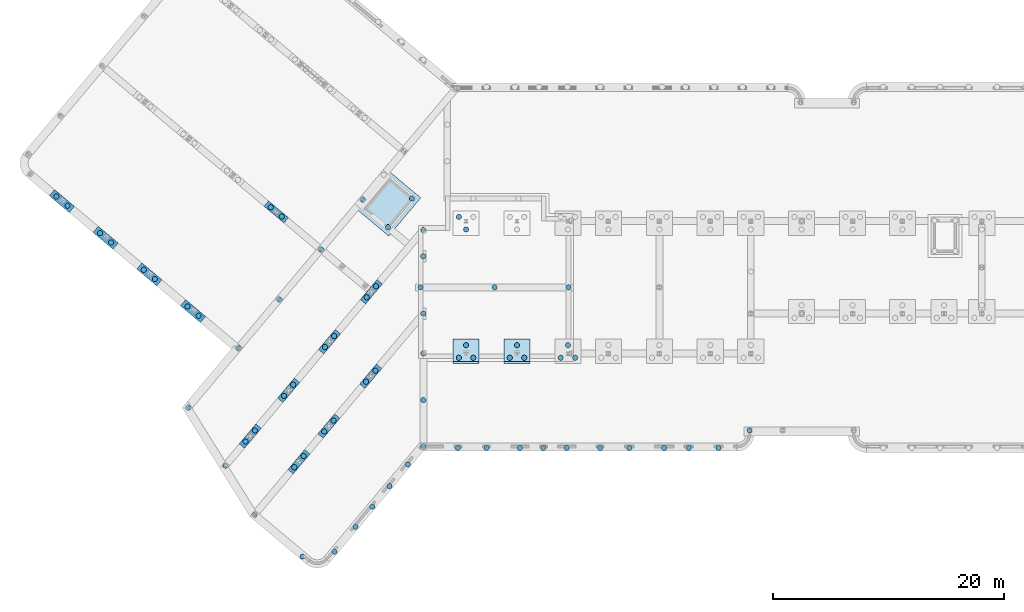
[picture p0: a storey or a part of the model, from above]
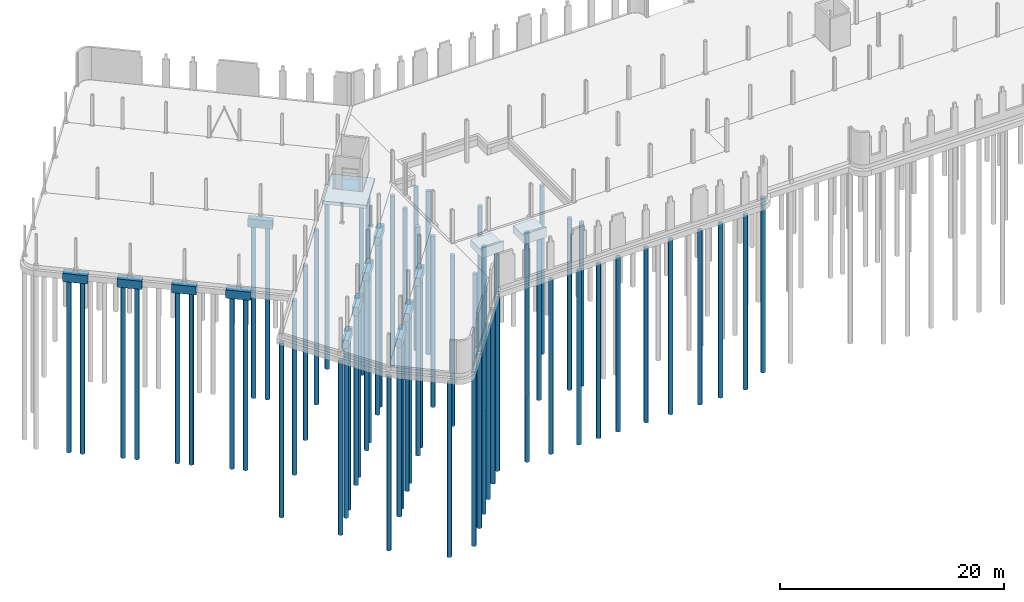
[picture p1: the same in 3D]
Properties of the parts of a building model (IFC2X3), part 1 of 3

# File
Description: ViewDefinition [CoordinationView_V2.0, QuantityTakeOffAddOnView], RevitIdentifiers [ContentGUID: 3bbd01f3-17ad-4578-aeb0-1501959cfa29, VersionGUID: ad77fbda-3d01-4379-a9cd-0f24ddc18399, NumberOfSaves: 457]
File name: MM25146_MFA Rijpelberg Helmond.ifc
Time: 2026-06-18T10:10:07+01:00
Written by: ODA SDAI 24.6
Made in: Autodesk Revit 24.3.0.13 (ENU) - IFC 24.3.0.13

# IfcProject, MM25146
LongName: MFA Rijpelberg; Phase: Project Status

# IfcSite, Default
RefLatitude: 42, 23, 13, 199999; RefLongitude: -71, -14, -31, -199999; RefElevation: 0 mm

# IfcSite: NLRS_00_GM_nulpunt_banier_blok_AT:nulpunt, NLRS_00_GM_nulpunt_banier_blok_AT:nulpunt:329284
Material: z9_Tielemans-grijs, z9_Tielemans-geel, z9_Tielemans-l-grijs
BaseQuantities - GrossArea: 4.78253 m2

# IfcBuilding, AT constructie
LongName: AT constructie

# IfcBuildingStorey: Level:A_hoogte_2.0mm (6)
In: AT constructie
Name | LongName | Elevation (mm)
-01 kelder | -01 kelder | -3500
00 begane grond | 00 begane grond | -1.08287e-12
01 eerste verdieping | 01 eerste verdieping | 3864
02 tweede verdieping | 02 tweede verdieping | 7728
03 derde verdieping | 03 derde verdieping | 12043
04 vierde verdieping | 04 vierde verdieping | 15456

# IfcBeam: balk HE_gen_HEA180 (37)
Classification: 28.11 hoofddraagconstructies; kolommen en liggers, kolom-/liggerconstructies (Uniformat); Material: h2_staal_S355
Tielemans_Framing_PSET - Soortelijk_gewicht: 8000 kg/m3; Type: balk HE_gen_HEA180; Description: HEA180; Structural Material: h2_staal_S355; Assembly Code: 28.11; Assembly Description: hoofddraagconstructies; kolommen en liggers, kolom-/liggerconstructies; Phase Created: 2. nieuwbouw; Staalkwaliteit: S355
Name (NLRS_28_SF_LIB_balk HEA_gen_AT:balk HE_gen_HEA180:...) | In | Length (mm) | CrossSectionArea (m2) | OuterSurfaceArea (m2) | GrossVolume (m3) | NetVolume (m3) = Volume (m3) | Massa (kg)
860012 | 01 eerste verdieping | 5893.25 | 0.00452527 | 6.03615 | 0.0266686 | 0.026668 | 213.344
911190 | 02 tweede verdieping | 23195 | 0.00452527 | 23.7574 | 0.104964 | 0.104961 | 839.691
911191 | 02 tweede verdieping | 20800 | 0.00452527 | 21.3044 | 0.0941257 | 0.0941235 | 752.988
913779 | 01 eerste verdieping | 20770 | 0.00452527 | 21.2736 | 0.0939899 | 0.0939878 | 751.902
917035 | 02 tweede verdieping | 4730 | 0.00452527 | 4.84469 | 0.0214045 | 0.0214041 | 171.232
918010 | 02 tweede verdieping |  |  |  |  | 0.00788246 | 63.0597 | BaseQuantities - GrossSurfaceArea: 0 m2
919803 | 02 tweede verdieping | 4730 | 0.00452527 | 4.84469 | 0.0214045 | 0.0214041 | 171.232
927900 | 02 tweede verdieping | 5573.25 | 0.00452527 | 5.70839 | 0.0252205 | 0.0252199 | 201.759
931741 | 03 derde verdieping | 9724.56 | 0.00452527 | 9.96036 | 0.0440063 | 0.0440053 | 352.042
931742 | 03 derde verdieping |  |  |  |  | 0.00806824 | 64.5459 | BaseQuantities - GrossSurfaceArea: 0 m2
932789 | 03 derde verdieping | 23440 | 0.00452527 | 24.0084 | 0.106072 | 0.10607 | 848.56
933283 | 03 derde verdieping |  |  |  |  | 0.00751662 | 60.1329 | BaseQuantities - GrossSurfaceArea: 0 m2
933658 | 03 derde verdieping | 11150 | 0.00452527 | 11.4204 | 0.0504569 | 0.0504557 | 403.646
943029 | 01 eerste verdieping | 11069 | 0.00452527 | 11.3374 | 0.0500904 | 0.0500893 | 400.714
957652 | 03 derde verdieping | 17066.3 | 0.00452527 | 17.4801 | 0.0772295 | 0.0772278 | 617.822
959066 | 03 derde verdieping | 10926.4 | 0.00452527 | 11.1913 | 0.0494449 | 0.0494438 | 395.55
959180 | 03 derde verdieping | 23215 | 0.00452527 | 23.7779 | 0.105054 | 0.105052 | 840.415
960760 | 03 derde verdieping |  |  |  |  | 0.00790709 | 63.2567 | BaseQuantities - GrossSurfaceArea: 0 m2
961026 | 03 derde verdieping | 8920 | 0.00452527 | 9.13629 | 0.0403654 | 0.0403645 | 322.916
961942 | 03 derde verdieping | 9849.99 | 0.00452527 | 10.0888 | 0.0445739 | 0.0445729 | 356.583
964484 | 03 derde verdieping | 16851.2 | 0.00452527 | 17.2598 | 0.0762563 | 0.0762546 | 610.037
964938 | 03 derde verdieping | 8920 | 0.00452527 | 9.13629 | 0.0403654 | 0.0403645 | 322.916
965281 | 03 derde verdieping |  |  |  |  | 0.00789343 | 63.1475 | BaseQuantities - GrossSurfaceArea: 0 m2
969872 | 03 derde verdieping | 11150 | 0.00452527 | 11.4204 | 0.0504569 | 0.0504557 | 403.646
969873 | 03 derde verdieping | 12611.9 | 0.00452527 | 12.9177 | 0.0570723 | 0.057071 | 456.568
980927 | 03 derde verdieping |  |  |  |  | 0.00787984 | 63.0387 | BaseQuantities - GrossSurfaceArea: 0 m2
980930 | 03 derde verdieping | 3475.1 | 0.00452527 | 3.55936 | 0.0157258 | 0.0157254 | 125.803
981139 | 03 derde verdieping | 5334.1 | 0.00452527 | 5.46344 | 0.0241383 | 0.0241377 | 193.102
981366 | 03 derde verdieping | 4194.6 | 0.00452527 | 4.29631 | 0.0189817 | 0.0189813 | 151.85
981455 | 03 derde verdieping | 5434.6 | 0.00452527 | 5.56638 | 0.0245931 | 0.0245925 | 196.74
981598 | 03 derde verdieping |  |  |  |  | 0.00787984 | 63.0387 | BaseQuantities - GrossSurfaceArea: 0 m2
981675 | 03 derde verdieping |  |  |  |  | 0.00787984 | 63.0387 | BaseQuantities - GrossSurfaceArea: 0 m2
981676 | 03 derde verdieping | 5434.6 | 0.00452527 | 5.56638 | 0.0245931 | 0.0245925 | 196.74
981677 | 03 derde verdieping |  |  |  |  | 0.00787984 | 63.0387 | BaseQuantities - GrossSurfaceArea: 0 m2
981806 | 03 derde verdieping | 3475.1 | 0.00452527 | 3.55936 | 0.0157258 | 0.0157254 | 125.803
981807 | 03 derde verdieping | 5334.1 | 0.00452527 | 5.46344 | 0.0241383 | 0.0241377 | 193.102
981808 | 03 derde verdieping | 4194.6 | 0.00452527 | 4.29631 | 0.0189817 | 0.0189813 | 151.85

# IfcBeam: balk HE_gen_HEB180 (5)
Classification: 28.11.21 (Uniformat); Material: h2_staal_S355
BaseQuantities - CrossSectionArea: 0.00652527 m2
Tielemans_Framing_PSET - Soortelijk_gewicht: 8000 kg/m3; Type: balk HE_gen_HEB180; Description: HEB180; Structural Material: h2_staal_S355; Assembly Code: 28.11.21; Phase Created: 2. nieuwbouw; Staalkwaliteit: S355
Name (NLRS_28_SF_LIB_balk HEB_gen_AT:balk HE_gen_HEB180:...) | In | Length (mm) | OuterSurfaceArea (m2) | GrossVolume (m3) | NetVolume (m3) = Volume (m3) | Massa (kg)
880518 | 01 eerste verdieping | 3400 | 3.52664 | 0.0221859 | 0.0221856 | 177.485
881305 | 01 eerste verdieping | 3400 | 3.52664 | 0.0221859 | 0.0221856 | 177.485
881423 | 01 eerste verdieping | 2670 | 2.76945 | 0.0174225 | 0.0174222 | 139.378
926703 | 02 tweede verdieping | 2400 | 2.48939 | 0.0156607 | 0.0156604 | 125.283
927702 | 02 tweede verdieping | 2400 | 2.48939 | 0.0156607 | 0.0156604 | 125.283

# IfcBeam: balk HE_gen_HEB260 (51)
Classification: 28.11.21 (Uniformat); Material: h2_staal_S355
Tielemans_Framing_PSET - LoadBearing: yes; Soortelijk_gewicht: 8000 kg/m3; Type: balk HE_gen_HEB260; Description: HEB260; Structural Material: h2_staal_S355; Assembly Code: 28.11.21; Phase Created: 2. nieuwbouw; Staalkwaliteit: S355
Name (NLRS_28_SF_LIB_balk HEB_gen_AT:balk HE_gen_HEB260:...) | In | Length (mm) | CrossSectionArea (m2) | OuterSurfaceArea (m2) | GrossVolume (m3) | NetVolume (m3) = Volume (m3) | Massa (kg)
838541 | 01 eerste verdieping | 38852 | 0.0118448 | 58.2312 | 0.460193 | 0.460183 | 3681.46
839623 | 01 eerste verdieping | 64336 | 0.0118448 | 96.4266 | 0.762045 | 0.762029 | 6096.23
840232 | 01 eerste verdieping | 28280 | 0.0118448 | 42.386 | 0.33497 | 0.334963 | 2679.7
840288 | 01 eerste verdieping | 7740 | 0.0118448 | 11.6007 | 0.0916785 | 0.0916765 | 733.412
840804 | 01 eerste verdieping | 7740 | 0.0118448 | 11.6007 | 0.0916785 | 0.0916765 | 733.412
841099 | 01 eerste verdieping | 3190 | 0.0118448 | 4.78116 | 0.0377848 | 0.037784 | 302.272
842198 | 01 eerste verdieping | 2751.5 | 0.0118448 | 4.12394 | 0.0325909 | 0.0325902 | 260.721
843266 | 01 eerste verdieping | 9253 | 0.0118448 | 13.8684 | 0.1096 | 0.109597 | 876.778
843785 | 01 eerste verdieping | 4853 | 0.0118448 | 7.27366 | 0.0574827 | 0.0574814 | 459.851
845937 | 01 eerste verdieping | 22819.5 | 0.0118448 | 34.2018 | 0.270292 | 0.270286 | 2162.29
849311 | 01 eerste verdieping | 27805.7 | 0.0118448 | 41.6752 | 0.329353 | 0.329346 | 2634.76
849494 | 01 eerste verdieping | 5382.3 | 0.0118448 | 8.06697 | 0.0637521 | 0.0637507 | 510.006
850513 | 01 eerste verdieping | 5400 | 0.0118448 | 8.0935 | 0.0639618 | 0.0639604 | 511.683
850850 | 01 eerste verdieping | 9120 | 0.0118448 | 13.669 | 0.108024 | 0.108022 | 864.176
851366 | 01 eerste verdieping | 5605 | 0.0118448 | 8.40075 | 0.0663899 | 0.0663885 | 531.108
871421 | 01 eerste verdieping | 7740 | 0.0118448 | 11.6007 | 0.0916785 | 0.0916765 | 733.412
872242 | 01 eerste verdieping | 2170 | 0.0118448 | 3.25239 | 0.0257032 | 0.0257026 | 205.621
872539 | 01 eerste verdieping | 6975 | 0.0118448 | 10.4541 | 0.0826173 | 0.0826155 | 660.924
873546 | 01 eerste verdieping | 2771 | 0.0118448 | 4.15316 | 0.0328219 | 0.0328212 | 262.569
877226 | 01 eerste verdieping | 2246.5 | 0.0118448 | 3.36705 | 0.0266093 | 0.0266087 | 212.87
906544 | 02 tweede verdieping | 9253 | 0.0118448 | 13.8684 | 0.1096 | 0.109597 | 876.778
906576 | 02 tweede verdieping | 4853 | 0.0118448 | 7.27366 | 0.0574827 | 0.0574814 | 459.851
906943 | 02 tweede verdieping | 38852 | 0.0118448 | 58.2312 | 0.460193 | 0.460183 | 3681.46
906945 | 02 tweede verdieping | 66850 | 0.0118448 | 100.195 | 0.791823 | 0.791806 | 6334.45
906946 | 02 tweede verdieping | 28267.3 | 0.0118448 | 42.3669 | 0.33482 | 0.334812 | 2678.5
906948 | 02 tweede verdieping | 7740 | 0.0118448 | 11.6007 | 0.0916785 | 0.0916765 | 733.412
906950 | 02 tweede verdieping | 7740 | 0.0118448 | 11.6007 | 0.0916785 | 0.0916765 | 733.412
906952 | 02 tweede verdieping | 3190 | 0.0118448 | 4.78116 | 0.0377848 | 0.037784 | 302.272
906963 | 02 tweede verdieping | 7740 | 0.0118448 | 11.6007 | 0.0916785 | 0.0916765 | 733.412
906964 | 02 tweede verdieping | 2246.5 | 0.0118448 | 3.36705 | 0.0266093 | 0.0266087 | 212.87
916128 | 01 eerste verdieping |  |  |  |  | 0.0200736 | 160.588 | BaseQuantities - GrossSurfaceArea: 0 m2
919917 | 02 tweede verdieping | 22819.5 | 0.0118448 | 34.2018 | 0.270292 | 0.270286 | 2162.29
921172 | 02 tweede verdieping | 7740 | 0.0118448 | 11.6007 | 0.0916785 | 0.0916765 | 733.412
921181 | 02 tweede verdieping | 7740 | 0.0118448 | 11.6007 | 0.0916785 | 0.0916765 | 733.412
921190 | 02 tweede verdieping | 7740 | 0.0118448 | 11.6007 | 0.0916785 | 0.0916765 | 733.412
921523 | 02 tweede verdieping | 7740 | 0.0118448 | 11.6007 | 0.0916785 | 0.0916765 | 733.412
922173 | 02 tweede verdieping | 2450 | 0.0118448 | 3.67205 | 0.0290197 | 0.0290191 | 232.152
924173 | 02 tweede verdieping | 24637.5 | 0.0118448 | 36.9266 | 0.291826 | 0.291819 | 2334.55
925254 | 02 tweede verdieping | 6975 | 0.0118448 | 10.4541 | 0.0826173 | 0.0826155 | 660.924
926347 | 02 tweede verdieping | 6975 | 0.0118448 | 10.4541 | 0.0826173 | 0.0826155 | 660.924
927266 | 02 tweede verdieping | 2400 | 0.0118448 | 3.59711 | 0.0284275 | 0.0284268 | 227.415
927459 | 02 tweede verdieping | 6975 | 0.0118448 | 10.4541 | 0.0826173 | 0.0826155 | 660.924
927622 | 02 tweede verdieping | 2400 | 0.0118448 | 3.59711 | 0.0284275 | 0.0284268 | 227.415
929418 | 03 derde verdieping | 24702.5 | 0.0118448 | 37.024 | 0.292595 | 0.292589 | 2340.71
935203 | 02 tweede verdieping | 4720 | 0.0118448 | 7.07432 | 0.0559073 | 0.0559061 | 447.249
935204 | 02 tweede verdieping | 5605 | 0.0118448 | 8.40075 | 0.0663899 | 0.0663885 | 531.108
936195 | 02 tweede verdieping | 5420 | 0.0118448 | 8.12348 | 0.0641987 | 0.0641973 | 513.578
946328 | 01 eerste verdieping | 11190 | 0.0118448 | 16.7715 | 0.132543 | 0.13254 | 1060.32
1006723 | 02 tweede verdieping | 28098.4 | 0.0118448 | 42.1138 | 0.33282 | 0.332812 | 2662.5
1068634 | 02 tweede verdieping | 4390 | 0.0118448 | 6.57972 | 0.0519985 | 0.0519974 | 415.979
1070116 | 02 tweede verdieping | 4370 | 0.0118448 | 6.54974 | 0.0517617 | 0.0517605 | 414.084

# IfcBeam: balk HE_gen_HEB320 (13)
Classification: 28.11 hoofddraagconstructies; kolommen en liggers, kolom-/liggerconstructies (Uniformat); Material: h2_staal_S355
Tielemans_Framing_PSET - LoadBearing: yes; Soortelijk_gewicht: 8000 kg/m3; Type: balk HE_gen_HEB320; Description: HEB320; Structural Material: h2_staal_S355; Assembly Code: 28.11; Assembly Description: hoofddraagconstructies; kolommen en liggers, kolom-/liggerconstructies; Phase Created: 2. nieuwbouw; Staalkwaliteit: S355
Name (NLRS_28_SF_LIB_balk HEB_gen_AT:balk HE_gen_HEB320:...) | In | Length (mm) | CrossSectionArea (m2) | OuterSurfaceArea (m2) | GrossVolume (m3) | NetVolume (m3) = Volume (m3) | Massa (kg)
844100 | 01 eerste verdieping | 27590 | 0.0161347 | 48.8521 | 0.445157 | 0.445147 | 3561.18
853093 | 01 eerste verdieping | 21985 | 0.0161347 | 38.9277 | 0.354722 | 0.354714 | 2837.71
854306 | 01 eerste verdieping | 7156.03 | 0.0161347 | 12.6708 | 0.11546 | 0.115458 | 923.664
855136 | 01 eerste verdieping | 24637.5 | 0.0161347 | 43.6243 | 0.397519 | 0.397511 | 3180.08
859108 | 01 eerste verdieping | 24637.5 | 0.0161347 | 43.6243 | 0.397519 | 0.397511 | 3180.08
859119 | 01 eerste verdieping | 23437.5 | 0.0161347 | 41.4995 | 0.378157 | 0.378149 | 3025.19
859419 | 01 eerste verdieping | 255 | 0.0161347 | 0.451515 | 0.00411435 | 0.00411426 | 32.9141
880048 | 01 eerste verdieping | 11190 | 0.0161347 | 19.8135 | 0.180547 | 0.180544 | 1444.35
906956 | 02 tweede verdieping | 27580 | 0.0161347 | 48.8344 | 0.444995 | 0.444986 | 3559.89
909027 | 02 tweede verdieping | 29672.6 | 0.0161347 | 52.5396 | 0.478758 | 0.478748 | 3829.99
915577 | 01 eerste verdieping |  |  |  |  | 0.0266108 | 212.887 | BaseQuantities - GrossSurfaceArea: 0 m2
921707 | 02 tweede verdieping | 11190 | 0.0161347 | 19.8135 | 0.180547 | 0.180544 | 1444.35
921989 | 02 tweede verdieping | 11190 | 0.0161347 | 19.8135 | 0.180547 | 0.180544 | 1444.35

# IfcBeam: balk HE_gen_HEB400, NLRS_28_SF_LIB_balk HEB_gen_AT:balk HE_gen_HEB400:847183
In: 01 eerste verdieping
Classification: 28.11 hoofddraagconstructies; kolommen en liggers, kolom-/liggerconstructies (Uniformat); Material: h2_staal_S355
BaseQuantities - Length: 8900 mm; CrossSectionArea: 0.0197782 m2; OuterSurfaceArea: 17.1471 m2; GrossVolume: 0.176026 m3; NetVolume: 0.176023 m3
Tielemans_Framing_PSET - Soortelijk_gewicht: 8000 kg/m3; Type: balk HE_gen_HEB400; Description: HEB400; Structural Material: h2_staal_S355; Assembly Code: 28.11; Assembly Description: hoofddraagconstructies; kolommen en liggers, kolom-/liggerconstructies; Phase Created: 2. nieuwbouw; Staalkwaliteit: S355; Volume: 0.176023 m3; Massa: 1408.18 kg

# IfcBeam: balk IPE_gen_270 (5)
Classification: 28.11.21 (Uniformat); Material: h2_staal_S355
BaseQuantities - CrossSectionArea: 0.00459466 m2
Tielemans_Framing_PSET - Soortelijk_gewicht: 8000 kg/m3; Type: balk IPE_gen_270; Description: IPE270; Structural Material: h2_staal_S355; Assembly Code: 28.11.21; Phase Created: 2. nieuwbouw; Staalkwaliteit: S355
Name (NLRS_28_SF_LIB_balk IPE_gen_AT:balk IPE_gen_270:...) | In | Length (mm) | OuterSurfaceArea (m2) | GrossVolume (m3) | NetVolume (m3) = Volume (m3) | Massa (kg)
959507 | 03 derde verdieping | 7025.9 | 7.3143 | 0.0322816 | 0.0322807 | 258.246
965756 | 01 eerste verdieping | 6830.2 | 7.11057 | 0.0313825 | 0.0313816 | 251.053
965876 | 01 eerste verdieping | 6830.2 | 7.11057 | 0.0313825 | 0.0313816 | 251.053
965905 | 01 eerste verdieping | 6830.2 | 7.11057 | 0.0313825 | 0.0313816 | 251.053
965943 | 01 eerste verdieping | 6830.2 | 7.11057 | 0.0313825 | 0.0313816 | 251.053

# IfcBeam: balk IPE_gen_330 (9)
In: 03 derde verdieping
Classification: 28.11.21 (Uniformat); Material: h2_staal_S355
BaseQuantities - CrossSectionArea: 0.00626086 m2
Tielemans_Framing_PSET - Soortelijk_gewicht: 8000 kg/m3; Type: balk IPE_gen_330; Description: IPE330; Structural Material: h2_staal_S355; Assembly Code: 28.11.21; Phase Created: 2. nieuwbouw; Staalkwaliteit: S355
Name (NLRS_28_SF_LIB_balk IPE_gen_AT:balk IPE_gen_330:...) | Length (mm) | OuterSurfaceArea (m2) | GrossVolume (m3) | NetVolume (m3) = Volume (m3) | Massa (kg)
966648 | 10160 | 12.7416 | 0.0636103 | 0.0636084 | 508.867
967036 | 10160 | 12.7416 | 0.0636103 | 0.0636084 | 508.867
967044 | 10160 | 12.7416 | 0.0636103 | 0.0636084 | 508.867
967054 | 10160 | 12.7416 | 0.0636103 | 0.0636084 | 508.867
970583 | 10160 | 12.7416 | 0.0636103 | 0.0636084 | 508.867
980111 | 7898 | 9.90486 | 0.0494483 | 0.0494467 | 395.574
980261 | 7898 | 9.90486 | 0.0494483 | 0.0494467 | 395.574
980269 | 7898 | 9.90486 | 0.0494483 | 0.0494467 | 395.574
980419 | 7898 | 9.90486 | 0.0494483 | 0.0494467 | 395.574

# IfcBeam: balk hout gelamineerd_gen_bxh 240x1600/1777 GL28c (4)
In: 03 derde verdieping
Classification: 28.11 hoofddraagconstructies; kolommen en liggers, kolom-/liggerconstructies (Uniformat); Material: i4_hout_gen
BaseQuantities - Length: 22090 mm; CrossSectionArea: 0.42648 m2; OuterSurfaceArea: 89.1111 m2; GrossVolume: 9.42094 m3; NetVolume: 8.95249 m3
Tielemans_Framing_PSET - Type: balk hout gelamineerd_gen_bxh 240x1600/1777 GL28c; Description: gelamineerde ligger 240x1600; Structural Material: i4_hout_gen; Assembly Code: 28.11; Assembly Description: hoofddraagconstructies; kolommen en liggers, kolom-/liggerconstructies; Phase Created: 2. nieuwbouw; Sterkteklasse: gen; Volume: 8.95249 m3; Soortelijk_gewicht: 500 kg/m3; Massa: 4476.25 kg
Name (NLRS_28_SF_LIB_balk hout gelamineerd_gen_AT:balk hout gelamineerd_gen_bxh 240x1600/1777 GL28c:...) | Group
931110 | Model Group:gelamineerligger:956931
957048 | Model Group:gelamineerligger:957069
957128 | Model Group:gelamineerligger:957141
957167 | Model Group:gelamineerligger:957180

# IfcBeam: balk strip liggend_gen_120x10 (50)
Classification: 28.11.21 (Uniformat); Material: h2_staal_S355
BaseQuantities - CrossSectionArea: 0.0012 m2
Tielemans_Framing_PSET - Soortelijk_gewicht: 8000 kg/m3; Type: balk strip liggend_gen_120x10; Description: ⌃120x10; Structural Material: h2_staal_S355; Assembly Code: 28.11.21; Phase Created: 2. nieuwbouw; Staalkwaliteit: S355
Name (NLRS_28_SF_LIB_balk strip_gen_AT:balk strip liggend_gen_120x10:...) | In | Length (mm) | OuterSurfaceArea (m2) | GrossVolume (m3) = NetVolume (m3) = Volume (m3) | Massa (kg)
871526 | 01 eerste verdieping | 5431.23 | 1.41212 | 0.00651748 | 52.1398
871527 | 01 eerste verdieping | 5431.23 | 1.41212 | 0.00651748 | 52.1398
871528 | 01 eerste verdieping | 5371.45 | 1.39658 | 0.00644574 | 51.5659
883360 | 01 eerste verdieping | 5487.06 | 1.42664 | 0.00658448 | 52.6758
883483 | 01 eerste verdieping | 5534.93 | 1.43908 | 0.00664191 | 53.1353
886345 | 01 eerste verdieping | 6134.56 | 1.59499 | 0.00736148 | 58.8918
886346 | 01 eerste verdieping | 6170.28 | 1.60427 | 0.00740433 | 59.2347
887414 | 01 eerste verdieping | 5074.28 | 1.31931 | 0.00608913 | 48.713
887415 | 01 eerste verdieping | 5169.63 | 1.3441 | 0.00620355 | 49.6284
900514 | 02 tweede verdieping | 8880.09 | 2.30882 | 0.0106561 | 85.2489
900515 | 02 tweede verdieping | 5074.28 | 1.31931 | 0.00608913 | 48.713
900516 | 02 tweede verdieping | 5074.28 | 1.31931 | 0.00608913 | 48.713
900519 | 02 tweede verdieping | 5074.28 | 1.31931 | 0.00608913 | 48.713
900520 | 02 tweede verdieping | 5074.28 | 1.31931 | 0.00608913 | 48.713
911194 | 02 tweede verdieping | 5701.28 | 1.48233 | 0.00684154 | 54.7323
911195 | 02 tweede verdieping | 6015.19 | 1.56395 | 0.00721823 | 57.7458
911196 | 02 tweede verdieping | 6116.43 | 1.59027 | 0.00733972 | 58.7178
911197 | 02 tweede verdieping | 6412.27 | 1.66719 | 0.00769472 | 61.5578
911642 | 02 tweede verdieping | 5545.38 | 1.4418 | 0.00665446 | 53.2357
911643 | 02 tweede verdieping | 5409.83 | 1.40656 | 0.0064918 | 51.9344
931221 | 03 derde verdieping | 6331.09 | 1.64608 | 0.00759731 | 60.7785
931222 | 03 derde verdieping | 6368.62 | 1.65584 | 0.00764235 | 61.1388
932307 | 03 derde verdieping | 5860 | 1.5236 | 0.007032 | 56.256
932308 | 03 derde verdieping | 5984.09 | 1.55586 | 0.00718091 | 57.4473
933737 | 03 derde verdieping | 6583.85 | 1.7118 | 0.00790062 | 63.205
933738 | 03 derde verdieping | 6420.35 | 1.66929 | 0.00770442 | 61.6353
947010 | 01 eerste verdieping | 6802.49 | 1.76865 | 0.00816299 | 65.3039
947011 | 01 eerste verdieping | 6802.49 | 1.76865 | 0.00816299 | 65.3039
947079 | 01 eerste verdieping | 6802.49 | 1.76865 | 0.00816299 | 65.3039
947080 | 01 eerste verdieping | 6802.49 | 1.76865 | 0.00816299 | 65.3039
948142 | 02 tweede verdieping | 5431.23 | 1.41212 | 0.00651748 | 52.1398
948143 | 02 tweede verdieping | 5431.23 | 1.41212 | 0.00651748 | 52.1398
948145 | 02 tweede verdieping | 5201.72 | 1.35245 | 0.00624207 | 49.9365
949156 | 01 eerste verdieping | 5737.63 | 1.49178 | 0.00688516 | 55.0813
949157 | 01 eerste verdieping | 5778.89 | 1.50251 | 0.00693467 | 55.4774
950411 | 02 tweede verdieping | 5431.23 | 1.41212 | 0.00651748 | 52.1398
950518 | 01 eerste verdieping | 5431.23 | 1.41212 | 0.00651748 | 52.1398
951115 | 01 eerste verdieping | 5732.21 | 1.49038 | 0.00687866 | 55.0293
951116 | 01 eerste verdieping | 5734.22 | 1.4909 | 0.00688107 | 55.0485
951269 | 02 tweede verdieping | 5732.21 | 1.49038 | 0.00687866 | 55.0293
951270 | 02 tweede verdieping | 5734.22 | 1.4909 | 0.00688107 | 55.0485
951681 | 02 tweede verdieping | 4855.23 | 1.26236 | 0.00582628 | 46.6102
951682 | 02 tweede verdieping | 4890.07 | 1.27142 | 0.00586809 | 46.9447
952182 | 02 tweede verdieping | 5737.63 | 1.49178 | 0.00688516 | 55.0813
952183 | 02 tweede verdieping | 5778.89 | 1.50251 | 0.00693467 | 55.4774
952999 | 02 tweede verdieping | 8880.09 | 2.30882 | 0.0106561 | 85.2489
983912 | 03 derde verdieping | 6621.18 | 1.72151 | 0.00794542 | 63.5633
983913 | 03 derde verdieping | 6624.63 | 1.7224 | 0.00794955 | 63.5964
984943 | 03 derde verdieping | 6621.18 | 1.72151 | 0.00794542 | 63.5633
984944 | 03 derde verdieping | 6624.63 | 1.7224 | 0.00794955 | 63.5964

# IfcBeam: balk strip liggend_gen_300x15 (7)
Classification: 28.11 hoofddraagconstructies; kolommen en liggers, kolom-/liggerconstructies (Uniformat); Material: h2_staal_S355
BaseQuantities - CrossSectionArea: 0.0045 m2
Tielemans_Framing_PSET - Soortelijk_gewicht: 8000 kg/m3; Type: balk strip liggend_gen_300x15; Description: ⌃300x15; Structural Material: h2_staal_S355; Assembly Code: 28.11; Assembly Description: hoofddraagconstructies; kolommen en liggers, kolom-/liggerconstructies; Phase Created: 2. nieuwbouw; Staalkwaliteit: S355
Name (NLRS_28_SF_LIB_balk strip_gen_AT:balk strip liggend_gen_300x15:...) | In | Length (mm) | OuterSurfaceArea (m2) | GrossVolume (m3) = NetVolume (m3) = Volume (m3) | Massa (kg)
847184 | 01 eerste verdieping | 8900 | 5.607 | 0.04005 | 320.4
863321 | 01 eerste verdieping | 832.254 | 0.52432 | 0.00374514 | 29.9612
881424 | 01 eerste verdieping | 2450 | 1.5435 | 0.011025 | 88.2
914541 | 01 eerste verdieping | 20660 | 13.0158 | 0.09297 | 743.76
926704 | 02 tweede verdieping | 2400 | 1.512 | 0.0108 | 86.4
927703 | 02 tweede verdieping | 2375 | 1.49625 | 0.0106875 | 85.5
928092 | 02 tweede verdieping | 5663.25 | 3.56785 | 0.0254846 | 203.877

# IfcBeam: balk strip liggend_gen_400x15 (27)
Classification: 28.11 hoofddraagconstructies; kolommen en liggers, kolom-/liggerconstructies (Uniformat); Material: h2_staal_S355
BaseQuantities - CrossSectionArea: 0.006 m2
Tielemans_Framing_PSET - Soortelijk_gewicht: 8000 kg/m3; Type: balk strip liggend_gen_400x15; Description: ⌃400x15; Structural Material: h2_staal_S355; Assembly Code: 28.11; Assembly Description: hoofddraagconstructies; kolommen en liggers, kolom-/liggerconstructies; Phase Created: 2. nieuwbouw; Staalkwaliteit: S355
Name (NLRS_28_SF_LIB_balk strip_gen_AT:balk strip liggend_gen_400x15:...) | In | Length (mm) | OuterSurfaceArea (m2) | GrossVolume (m3) = NetVolume (m3) = Volume (m3) | Massa (kg)
840289 | 01 eerste verdieping | 7600 | 6.308 | 0.0456 | 364.8
840805 | 01 eerste verdieping | 7500 | 6.225 | 0.045 | 360
842702 | 01 eerste verdieping | 2547.5 | 2.11442 | 0.015285 | 122.28
843267 | 01 eerste verdieping | 9253 | 7.67999 | 0.055518 | 444.144
843786 | 01 eerste verdieping | 4853 | 4.02799 | 0.029118 | 232.944
870829 | 01 eerste verdieping | 4040.5 | 3.35361 | 0.024243 | 193.944
871422 | 01 eerste verdieping | 2193 | 1.82019 | 0.013158 | 105.264
872243 | 01 eerste verdieping | 2170 | 1.8011 | 0.01302 | 104.16
872540 | 01 eerste verdieping | 4661 | 3.86863 | 0.027966 | 223.728
880959 | 01 eerste verdieping | 3200 | 2.656 | 0.0192 | 153.6
906545 | 02 tweede verdieping | 9253 | 7.67999 | 0.055518 | 444.144
906577 | 02 tweede verdieping | 4853 | 4.02799 | 0.029118 | 232.944
906966 | 02 tweede verdieping | 2193 | 1.82019 | 0.013158 | 105.264
909855 | 02 tweede verdieping | 4040.5 | 3.35361 | 0.024243 | 193.944
921173 | 02 tweede verdieping | 7500 | 6.225 | 0.045 | 360
921182 | 02 tweede verdieping | 7500 | 6.225 | 0.045 | 360
921191 | 02 tweede verdieping | 7500 | 6.225 | 0.045 | 360
921597 | 02 tweede verdieping | 7500 | 6.225 | 0.045 | 360
925255 | 02 tweede verdieping | 6641 | 5.51203 | 0.039846 | 318.768
926348 | 02 tweede verdieping | 6641 | 5.51203 | 0.039846 | 318.768
927267 | 02 tweede verdieping | 2400 | 1.992 | 0.0144 | 115.2
927460 | 02 tweede verdieping | 6641 | 5.51203 | 0.039846 | 318.768
927623 | 02 tweede verdieping | 2395 | 1.98785 | 0.01437 | 114.96
986487 | 02 tweede verdieping | 2450 | 2.0335 | 0.0147 | 117.6
986812 | 02 tweede verdieping | 2450 | 2.0335 | 0.0147 | 117.6
1110078 | 02 tweede verdieping | 2450 | 2.0335 | 0.0147 | 117.6
1110527 | 02 tweede verdieping | 2450 | 2.0335 | 0.0147 | 117.6

# IfcBeam: balk strip liggend_gen_420x15 (17)
Classification: 28.11 hoofddraagconstructies; kolommen en liggers, kolom-/liggerconstructies (Uniformat); Material: h2_staal_S355
Tielemans_Framing_PSET - Soortelijk_gewicht: 8000 kg/m3; Type: balk strip liggend_gen_420x15; Description: ⌃420x15; Structural Material: h2_staal_S355; Assembly Code: 28.11; Assembly Description: hoofddraagconstructies; kolommen en liggers, kolom-/liggerconstructies; Phase Created: 2. nieuwbouw; Staalkwaliteit: S355
Name (NLRS_28_SF_LIB_balk strip_gen_AT:balk strip liggend_gen_420x15:...) | In | Length (mm) | CrossSectionArea (m2) | OuterSurfaceArea (m2) | GrossVolume (m3) | NetVolume (m3) = Volume (m3) | Massa (kg)
838542 | 01 eerste verdieping | 8900 | 0.0063 | 7.743 | 0.05607 | 0.05607 | 448.56
839565 | 01 eerste verdieping | 8500 | 0.0063 | 7.395 | 0.05355 | 0.05355 | 428.4
849495 | 01 eerste verdieping | 5135 | 0.0063 | 4.46745 | 0.0323505 | 0.0323505 | 258.804
850514 | 01 eerste verdieping | 5365 | 0.0063 | 4.66755 | 0.0337995 | 0.0337995 | 270.396
850851 | 01 eerste verdieping | 4330 | 0.0063 | 3.7671 | 0.027279 | 0.027279 | 218.232
851336 | 01 eerste verdieping | 5505 | 0.0063 | 4.78935 | 0.0346815 | 0.0346815 | 277.452
857121 | 01 eerste verdieping | 4130 | 0.0063 | 3.5931 | 0.026019 | 0.026019 | 208.152
877227 | 01 eerste verdieping | 1969.5 | 0.0063 | 1.71346 | 0.0124078 | 0.0124078 | 99.2628
881306 | 01 eerste verdieping | 3140 | 0.0063 | 2.7318 | 0.019782 | 0.019782 | 158.256
906965 | 02 tweede verdieping | 1912.5 | 0.0063 | 1.66387 | 0.0120487 | 0.0120487 | 96.39
916427 | 01 eerste verdieping |  |  |  |  | 0.00990839 | 79.2671 | BaseQuantities - GrossSurfaceArea: 0 m2
922174 | 02 tweede verdieping | 2450 | 0.0063 | 2.1315 | 0.015435 | 0.015435 | 123.48
924172 | 02 tweede verdieping | 24517.5 | 0.0063 | 21.3302 | 0.15446 | 0.15446 | 1235.68
948220 | 02 tweede verdieping | 1969.5 | 0.0063 | 1.71346 | 0.0124078 | 0.0124078 | 99.2628
1067908 | 02 tweede verdieping | 5485 | 0.0063 | 4.77195 | 0.0345555 | 0.0345555 | 276.444
1067990 | 02 tweede verdieping | 4330 | 0.0063 | 3.7671 | 0.027279 | 0.027279 | 218.232
1068405 | 02 tweede verdieping | 4110 | 0.0063 | 3.5757 | 0.025893 | 0.025893 | 207.144

# IfcBeam: balk strip liggend_gen_420x20 (2)
In: 02 tweede verdieping
Classification: 28.11 hoofddraagconstructies; kolommen en liggers, kolom-/liggerconstructies (Uniformat); Material: h2_staal_S355
BaseQuantities - Length: 10950 mm; CrossSectionArea: 0.0084 m2; OuterSurfaceArea: 9.636 m2; GrossVolume: 0.09198 m3; NetVolume: 0.09198 m3
Tielemans_Framing_PSET - Soortelijk_gewicht: 8000 kg/m3; Type: balk strip liggend_gen_420x20; Description: ⌃420x20; Structural Material: h2_staal_S355; Assembly Code: 28.11; Assembly Description: hoofddraagconstructies; kolommen en liggers, kolom-/liggerconstructies; Phase Created: 2. nieuwbouw; Staalkwaliteit: S355; Volume: 0.09198 m3; Massa: 735.84 kg
Name (NLRS_28_SF_LIB_balk strip_gen_AT:balk strip liggend_gen_420x20:...)
921708
921990

# IfcBeam: balk strip liggend_gen_440x15, NLRS_28_SF_LIB_balk strip_gen_AT:balk strip liggend_gen_440x15:857523
In: 01 eerste verdieping
Classification: 28.11 hoofddraagconstructies; kolommen en liggers, kolom-/liggerconstructies (Uniformat); Material: h2_staal_S355
BaseQuantities - Length: 13565 mm; CrossSectionArea: 0.0066 m2; OuterSurfaceArea: 12.3442 m2; GrossVolume: 0.089529 m3; NetVolume: 0.089529 m3
Tielemans_Framing_PSET - Soortelijk_gewicht: 8000 kg/m3; Type: balk strip liggend_gen_440x15; Description: ⌃440x15; Structural Material: h2_staal_S355; Assembly Code: 28.11; Assembly Description: hoofddraagconstructies; kolommen en liggers, kolom-/liggerconstructies; Phase Created: 2. nieuwbouw; Staalkwaliteit: S355; Volume: 0.089529 m3; Massa: 716.232 kg

# IfcBeam: balk strip liggend_gen_440x20 (6)
Classification: 28.11 hoofddraagconstructies; kolommen en liggers, kolom-/liggerconstructies (Uniformat); Material: h2_staal_S355
Tielemans_Framing_PSET - LoadBearing: yes; Soortelijk_gewicht: 8000 kg/m3; Type: balk strip liggend_gen_440x20; Description: ⌃440x20; Structural Material: h2_staal_S355; Assembly Code: 28.11; Assembly Description: hoofddraagconstructies; kolommen en liggers, kolom-/liggerconstructies; Phase Created: 2. nieuwbouw; Staalkwaliteit: S355
Name (NLRS_28_SF_LIB_balk strip_gen_AT:balk strip liggend_gen_440x20:...) | In | Length (mm) | CrossSectionArea (m2) | OuterSurfaceArea (m2) | GrossVolume (m3) | NetVolume (m3) = Volume (m3) | Massa (kg)
847265 | 01 eerste verdieping | 12765 | 0.0088 | 11.7438 | 0.112332 | 0.112332 | 898.656
855135 | 01 eerste verdieping | 24537.5 | 0.0088 | 22.5745 | 0.21593 | 0.21593 | 1727.44
859118 | 01 eerste verdieping | 23317.5 | 0.0088 | 21.4521 | 0.205194 | 0.205194 | 1641.55
859420 | 01 eerste verdieping | 255 | 0.0088 | 0.2346 | 0.002244 | 0.002244 | 17.952
909023 | 02 tweede verdieping | 22375 | 0.0088 | 20.585 | 0.1969 | 0.1969 | 1575.2
913646 | 01 eerste verdieping |  |  |  |  | 0.0135466 | 108.373 | BaseQuantities - GrossSurfaceArea: 0 m2

# IfcBeam: balk strip liggend_gen_500x15 (24)
Classification: 28.11 hoofddraagconstructies; kolommen en liggers, kolom-/liggerconstructies (Uniformat); Material: h2_staal_S355
BaseQuantities - CrossSectionArea: 0.0075 m2
Tielemans_Framing_PSET - Type: balk strip liggend_gen_500x15; Description: ⌃500x15; Structural Material: h2_staal_S355; Assembly Code: 28.11; Assembly Description: hoofddraagconstructies; kolommen en liggers, kolom-/liggerconstructies; Phase Created: 2. nieuwbouw; Staalkwaliteit: S355; Soortelijk_gewicht: 8000 kg/m3
Name (NLRS_28_SF_LIB_balk strip_gen_AT:balk strip liggend_gen_500x15:...) | In | Length (mm) | OuterSurfaceArea (m2) | GrossVolume (m3) = NetVolume (m3) = Volume (m3) | Massa (kg)
836961 | 01 eerste verdieping | 28300 | 29.149 | 0.21225 | 1698
839320 | 01 eerste verdieping | 30072 | 30.9742 | 0.22554 | 1804.32
839707 | 01 eerste verdieping | 7120 | 7.3336 | 0.0534 | 427.2
840233 | 01 eerste verdieping | 28550 | 29.4065 | 0.214125 | 1713
841273 | 01 eerste verdieping | 2950 | 3.0385 | 0.022125 | 177
845938 | 01 eerste verdieping | 22745.9 | 23.4282 | 0.170594 | 1364.75
870762 | 01 eerste verdieping | 16161.5 | 16.6463 | 0.121211 | 969.69
877442 | 01 eerste verdieping | 5307 | 5.46621 | 0.0398025 | 318.42
906944 | 02 tweede verdieping | 30817 | 31.7415 | 0.231127 | 1849.02
906947 | 02 tweede verdieping | 28400 | 29.252 | 0.213 | 1704
906949 | 02 tweede verdieping | 7600 | 7.828 | 0.057 | 456
906951 | 02 tweede verdieping | 7500 | 7.725 | 0.05625 | 450
906953 | 02 tweede verdieping | 2950 | 3.0385 | 0.022125 | 177
906962 | 02 tweede verdieping | 18869.5 | 19.4356 | 0.141521 | 1132.17
907020 | 02 tweede verdieping | 1305 | 1.34415 | 0.0097875 | 78.3
907085 | 02 tweede verdieping | 28300 | 29.149 | 0.21225 | 1698
907086 | 02 tweede verdieping | 905 | 0.93215 | 0.0067875 | 54.3
907087 | 02 tweede verdieping | 7865 | 8.10095 | 0.0589875 | 471.9
946329 | 01 eerste verdieping | 10950 | 11.2785 | 0.082125 | 657
975772 | 02 tweede verdieping | 5307 | 5.46621 | 0.0398025 | 318.42
986860 | 02 tweede verdieping | 1950 | 2.0085 | 0.014625 | 117
1070283 | 02 tweede verdieping | 4110 | 4.2333 | 0.030825 | 246.6
1070398 | 02 tweede verdieping | 5135 | 5.28905 | 0.0385125 | 308.1
1110141 | 02 tweede verdieping | 1950 | 2.0085 | 0.014625 | 117

# IfcBeam: balk strip liggend_gen_540x15 (5)
Classification: 28.11 hoofddraagconstructies; kolommen en liggers, kolom-/liggerconstructies (Uniformat); Material: h2_staal_S355
BaseQuantities - CrossSectionArea: 0.0081 m2
Tielemans_Framing_PSET - LoadBearing: yes; Soortelijk_gewicht: 8000 kg/m3; Type: balk strip liggend_gen_540x15; Description: ⌃540x15; Structural Material: h2_staal_S355; Assembly Code: 28.11; Assembly Description: hoofddraagconstructies; kolommen en liggers, kolom-/liggerconstructies; Phase Created: 2. nieuwbouw; Staalkwaliteit: S355
Name (NLRS_28_SF_LIB_balk strip_gen_AT:balk strip liggend_gen_540x15:...) | In | Length (mm) | OuterSurfaceArea (m2) | GrossVolume (m3) = NetVolume (m3) = Volume (m3) | Massa (kg)
849312 | 01 eerste verdieping | 9990 | 11.0889 | 0.080919 | 647.352
873044 | 01 eerste verdieping | 2314 | 2.56854 | 0.0187434 | 149.947
882253 | 01 eerste verdieping | 4780.42 | 5.30626 | 0.0387214 | 309.771
919918 | 02 tweede verdieping | 22735.9 | 25.2368 | 0.18416 | 1473.28
1006724 | 02 tweede verdieping | 28335.4 | 31.4523 | 0.229517 | 1836.14

# IfcBeam: balk strip liggend_gen_560x20 (7)
Classification: 28.11 hoofddraagconstructies; kolommen en liggers, kolom-/liggerconstructies (Uniformat); Material: h2_staal_S355
BaseQuantities - CrossSectionArea: 0.0112 m2
Tielemans_Framing_PSET - Soortelijk_gewicht: 8000 kg/m3; Type: balk strip liggend_gen_560x20; Description: ⌃560x20; Structural Material: h2_staal_S355; Assembly Code: 28.11; Assembly Description: hoofddraagconstructies; kolommen en liggers, kolom-/liggerconstructies; Phase Created: 2. nieuwbouw; Staalkwaliteit: S355
Name (NLRS_28_SF_LIB_balk strip_gen_AT:balk strip liggend_gen_560x20:...) | In | Length (mm) | OuterSurfaceArea (m2) | GrossVolume (m3) = NetVolume (m3) = Volume (m3) | Massa (kg)
844101 | 01 eerste verdieping | 27342.5 | 31.7173 | 0.306236 | 2449.89
847676 | 01 eerste verdieping | 9220 | 10.6952 | 0.103264 | 826.112
853838 | 01 eerste verdieping | 7156.03 | 8.30099 | 0.0801475 | 641.18
859107 | 01 eerste verdieping | 24517.5 | 28.4403 | 0.274596 | 2196.77
880049 | 01 eerste verdieping | 11200 | 12.992 | 0.12544 | 1003.52
906957 | 02 tweede verdieping | 27272.1 | 31.6356 | 0.305447 | 2443.58
906958 | 02 tweede verdieping | 7297.57 | 8.46518 | 0.0817328 | 653.862

# IfcBeam: balk vierkant_gen_214x200 (2)
In: 01 eerste verdieping
Classification: 28.11 hoofddraagconstructies; kolommen en liggers, kolom-/liggerconstructies (Uniformat); Material: f2_beton_prefab_gen
BaseQuantities - CrossSectionArea: 0.0428 m2
Tielemans_Framing_PSET - LoadBearing: yes; Soortelijk_gewicht: 2500 kg/m3; Type: balk vierkant_gen_214x200; Description: pbl; Structural Material: f2_beton_prefab_gen; Assembly Code: 28.11; Assembly Description: hoofddraagconstructies; kolommen en liggers, kolom-/liggerconstructies; Phase Created: 2. nieuwbouw; Sterkteklasse: gen
Name (NLRS_28_SF_LIB_balk vierkant prefab_gen_AT:balk vierkant_gen_214x200:...) | Length (mm) | OuterSurfaceArea (m2) | GrossVolume (m3) = NetVolume (m3) = Volume (m3) | Massa (kg)
1056026 | 961.458 | 0.796087 | 0.0411504 | 102.876
1056309 | 780 | 0.64584 | 0.033384 | 83.46

# IfcBeam: balk vierkant_gen_214x544 pbl (110)
Classification: 28.11 hoofddraagconstructies; kolommen en liggers, kolom-/liggerconstructies (Uniformat); Material: f2_beton_prefab_gen
BaseQuantities - CrossSectionArea: 0.116416 m2
Tielemans_Framing_PSET - Type: balk vierkant_gen_214x544 pbl; Description: pbl; Structural Material: f2_beton_prefab_gen; Assembly Code: 28.11; Assembly Description: hoofddraagconstructies; kolommen en liggers, kolom-/liggerconstructies; LoadBearing: yes; Phase Created: 2. nieuwbouw; Sterkteklasse: gen; Soortelijk_gewicht: 2500 kg/m3
Name (NLRS_28_SF_LIB_balk vierkant prefab_gen_AT:balk vierkant_gen_214x544 pbl:...) | In | Length (mm) | OuterSurfaceArea (m2) | GrossVolume (m3) = NetVolume (m3) = Volume (m3) | Massa (kg)
828655 | 01 eerste verdieping | 2190 | 3.32004 | 0.254951 | 637.378
830669 | 01 eerste verdieping | 2190 | 3.32004 | 0.254951 | 637.378
830675 | 01 eerste verdieping | 2190 | 3.32004 | 0.254951 | 637.378
830681 | 01 eerste verdieping | 2190 | 3.32004 | 0.254951 | 637.378
830687 | 01 eerste verdieping | 2190 | 3.32004 | 0.254951 | 637.378
830693 | 01 eerste verdieping | 2190 | 3.32004 | 0.254951 | 637.378
830699 | 01 eerste verdieping | 2190 | 3.32004 | 0.254951 | 637.378
830705 | 01 eerste verdieping | 2190 | 3.32004 | 0.254951 | 637.378
830711 | 01 eerste verdieping | 2190 | 3.32004 | 0.254951 | 637.378
830717 | 01 eerste verdieping | 2190 | 3.32004 | 0.254951 | 637.378
830761 | 01 eerste verdieping | 1310 | 1.98596 | 0.152505 | 381.262
830913 | 01 eerste verdieping | 1310 | 1.98596 | 0.152505 | 381.262
830914 | 01 eerste verdieping | 2190 | 3.32004 | 0.254951 | 637.378
830915 | 01 eerste verdieping | 1430 | 2.16788 | 0.166475 | 416.187
830916 | 01 eerste verdieping | 2190 | 3.32004 | 0.254951 | 637.378
830917 | 01 eerste verdieping | 2190 | 3.32004 | 0.254951 | 637.378
830918 | 01 eerste verdieping | 2190 | 3.32004 | 0.254951 | 637.378
830919 | 01 eerste verdieping | 1303.01 | 1.97536 | 0.151691 | 379.228
830920 | 01 eerste verdieping | 1310 | 1.98596 | 0.152505 | 381.262
831020 | 01 eerste verdieping | 2190 | 3.32004 | 0.254951 | 637.378
831026 | 01 eerste verdieping | 2190 | 3.32004 | 0.254951 | 637.378
831032 | 01 eerste verdieping | 2190 | 3.32004 | 0.254951 | 637.378
831722 | 01 eerste verdieping | 2190 | 3.32004 | 0.254951 | 637.378
831945 | 01 eerste verdieping | 2190 | 3.32004 | 0.254951 | 637.378
831951 | 01 eerste verdieping | 2190 | 3.32004 | 0.254951 | 637.378
831957 | 01 eerste verdieping | 2190 | 3.32004 | 0.254951 | 637.378
831963 | 01 eerste verdieping | 2190 | 3.32004 | 0.254951 | 637.378
831969 | 01 eerste verdieping | 2190 | 3.32004 | 0.254951 | 637.378
832371 | 01 eerste verdieping | 2190 | 3.32004 | 0.254951 | 637.378
832372 | 01 eerste verdieping | 2190 | 3.32004 | 0.254951 | 637.378
832373 | 01 eerste verdieping | 2190 | 3.32004 | 0.254951 | 637.378
832374 | 01 eerste verdieping | 2190 | 3.32004 | 0.254951 | 637.378
832375 | 01 eerste verdieping | 2190 | 3.32004 | 0.254951 | 637.378
832376 | 01 eerste verdieping | 2190 | 3.32004 | 0.254951 | 637.378
832377 | 01 eerste verdieping | 2190 | 3.32004 | 0.254951 | 637.378
832378 | 01 eerste verdieping | 2190 | 3.32004 | 0.254951 | 637.378
832379 | 01 eerste verdieping | 2190 | 3.32004 | 0.254951 | 637.378
832380 | 01 eerste verdieping | 2190 | 3.32004 | 0.254951 | 637.378
832381 | 01 eerste verdieping | 1310 | 1.98596 | 0.152505 | 381.262
832532 | 01 eerste verdieping | 1310 | 1.98596 | 0.152505 | 381.262
832533 | 01 eerste verdieping | 2190 | 3.32004 | 0.254951 | 637.378
832534 | 01 eerste verdieping | 2190 | 3.32004 | 0.254951 | 637.378
832535 | 01 eerste verdieping | 1310 | 1.98596 | 0.152505 | 381.262
833208 | 01 eerste verdieping | 2190 | 3.32004 | 0.254951 | 637.378
833214 | 01 eerste verdieping | 2190 | 3.32004 | 0.254951 | 637.378
833220 | 01 eerste verdieping | 2190 | 3.32004 | 0.254951 | 637.378
833226 | 01 eerste verdieping | 2190 | 3.32004 | 0.254951 | 637.378
833275 | 01 eerste verdieping | 1310 | 1.98596 | 0.152505 | 381.262
833281 | 01 eerste verdieping | 1310 | 1.98596 | 0.152505 | 381.262
833287 | 01 eerste verdieping | 1310 | 1.98596 | 0.152505 | 381.262
834677 | 01 eerste verdieping | 2190 | 3.32004 | 0.254951 | 637.378
834811 | 01 eerste verdieping | 1430 | 2.16788 | 0.166475 | 416.187
834870 | 01 eerste verdieping | 1430 | 2.16788 | 0.166475 | 416.187
834876 | 01 eerste verdieping | 1400.41 | 2.12302 | 0.16303 | 407.574
865583 | 01 eerste verdieping | 2190 | 3.32004 | 0.254951 | 637.378
892131 | 02 tweede verdieping | 2190 | 3.32004 | 0.254951 | 637.378
892132 | 02 tweede verdieping | 2190 | 3.32004 | 0.254951 | 637.378
892133 | 02 tweede verdieping | 2190 | 3.32004 | 0.254951 | 637.378
892134 | 02 tweede verdieping | 2190 | 3.32004 | 0.254951 | 637.378
892135 | 02 tweede verdieping | 2190 | 3.32004 | 0.254951 | 637.378
892136 | 02 tweede verdieping | 2190 | 3.32004 | 0.254951 | 637.378
892137 | 02 tweede verdieping | 2190 | 3.32004 | 0.254951 | 637.378
892138 | 02 tweede verdieping | 2190 | 3.32004 | 0.254951 | 637.378
892139 | 02 tweede verdieping | 2190 | 3.32004 | 0.254951 | 637.378
892140 | 02 tweede verdieping | 2190 | 3.32004 | 0.254951 | 637.378
892141 | 02 tweede verdieping | 1310 | 1.98596 | 0.152505 | 381.262
892142 | 02 tweede verdieping | 2190 | 3.32004 | 0.254951 | 637.378
892143 | 02 tweede verdieping | 2190 | 3.32004 | 0.254951 | 637.378
892144 | 02 tweede verdieping | 2190 | 3.32004 | 0.254951 | 637.378
892145 | 02 tweede verdieping | 2190 | 3.32004 | 0.254951 | 637.378
892146 | 02 tweede verdieping | 2190 | 3.32004 | 0.254951 | 637.378
892147 | 02 tweede verdieping | 2190 | 3.32004 | 0.254951 | 637.378
892148 | 02 tweede verdieping | 2190 | 3.32004 | 0.254951 | 637.378
892149 | 02 tweede verdieping | 2071.12 | 3.13983 | 0.241112 | 602.78
892150 | 02 tweede verdieping | 2190 | 3.32004 | 0.254951 | 637.378
892151 | 02 tweede verdieping | 2190 | 3.32004 | 0.254951 | 637.378
892152 | 02 tweede verdieping | 2190 | 3.32004 | 0.254951 | 637.378
892154 | 02 tweede verdieping | 2190 | 3.32004 | 0.254951 | 637.378
892159 | 02 tweede verdieping | 2190 | 3.32004 | 0.254951 | 637.378
892160 | 02 tweede verdieping | 2190 | 3.32004 | 0.254951 | 637.378
892161 | 02 tweede verdieping | 2190 | 3.32004 | 0.254951 | 637.378
892162 | 02 tweede verdieping | 2190 | 3.32004 | 0.254951 | 637.378
892163 | 02 tweede verdieping | 2190 | 3.32004 | 0.254951 | 637.378
892164 | 02 tweede verdieping | 2190 | 3.32004 | 0.254951 | 637.378
892165 | 02 tweede verdieping | 2190 | 3.32004 | 0.254951 | 637.378
892166 | 02 tweede verdieping | 2190 | 3.32004 | 0.254951 | 637.378
892167 | 02 tweede verdieping | 2190 | 3.32004 | 0.254951 | 637.378
892168 | 02 tweede verdieping | 2190 | 3.32004 | 0.254951 | 637.378
892169 | 02 tweede verdieping | 1310 | 1.98596 | 0.152505 | 381.262
892170 | 02 tweede verdieping | 1310 | 1.98596 | 0.152505 | 381.262
892171 | 02 tweede verdieping | 2190 | 3.32004 | 0.254951 | 637.378
892172 | 02 tweede verdieping | 2190 | 3.32004 | 0.254951 | 637.378
892173 | 02 tweede verdieping | 1310 | 1.98596 | 0.152505 | 381.262
892174 | 02 tweede verdieping | 2190 | 3.32004 | 0.254951 | 637.378
892175 | 02 tweede verdieping | 2190 | 3.32004 | 0.254951 | 637.378
892176 | 02 tweede verdieping | 2190 | 3.32004 | 0.254951 | 637.378
892177 | 02 tweede verdieping | 2190 | 3.32004 | 0.254951 | 637.378
892178 | 02 tweede verdieping | 1310 | 1.98596 | 0.152505 | 381.262
892179 | 02 tweede verdieping | 1310 | 1.98596 | 0.152505 | 381.262
892180 | 02 tweede verdieping | 1310 | 1.98596 | 0.152505 | 381.262
892181 | 02 tweede verdieping | 2190 | 3.32004 | 0.254951 | 637.378
892182 | 02 tweede verdieping | 2190 | 3.32004 | 0.254951 | 637.378
892183 | 02 tweede verdieping | 2310 | 3.50196 | 0.268921 | 672.302
892184 | 02 tweede verdieping | 1228.66 | 1.86264 | 0.143035 | 357.588
892185 | 02 tweede verdieping | 2190 | 3.32004 | 0.254951 | 637.378
898780 | 01 eerste verdieping | 1310 | 1.98596 | 0.152505 | 381.262
898847 | 02 tweede verdieping | 1310 | 1.98596 | 0.152505 | 381.262
900033 | 02 tweede verdieping | 2190 | 3.32004 | 0.254951 | 637.378
906340 | 02 tweede verdieping | 2190 | 3.32004 | 0.254951 | 637.378
906495 | 02 tweede verdieping | 2190 | 3.32004 | 0.254951 | 637.378

# IfcBeam: balk_gen_K100x50x4 (5)
Classification: 28.11.21 (Uniformat); Material: h2_staal_S355
BaseQuantities - CrossSectionArea: 0.00494501 m2
Tielemans_Framing_PSET - Soortelijk_gewicht: 8000 kg/m3; Type: balk_gen_K100x50x4; Description: ⌄100x50x4; Structural Material: h2_staal_S355; Assembly Code: 28.11.21; Phase Created: 2. nieuwbouw; Staalkwaliteit: S355
Name (NLRS_28_SF_LIB_balk koker ongelijk_gen_AT:balk_gen_K100x50x4:...) | In | Length (mm) | OuterSurfaceArea (m2) | GrossVolume (m3) | NetVolume (m3) = Volume (m3) | Massa (kg)
885464 | 01 eerste verdieping | 3530.74 | 1.93272 | 0.0174596 | 0.00386541 | 30.9233
937257 | 01 eerste verdieping | 3412.24 | 1.86786 | 0.0168736 | 0.00373568 | 29.8854
937618 | 00 begane grond | 3769.48 | 2.0634 | 0.0186401 | 0.00412677 | 33.0142
937619 | 00 begane grond | 3746.43 | 2.05079 | 0.0185261 | 0.00410154 | 32.8123
951501 | 01 eerste verdieping | 5143.76 | 2.81569 | 0.025436 | 0.00563132 | 45.0506

# IfcBeam: balk_gen_K80x80x4 (11)
Classification: 28.11.21 (Uniformat); Material: h2_staal_S355
BaseQuantities - CrossSectionArea: 0.00633041 m2
Tielemans_Framing_PSET - Soortelijk_gewicht: 8000 kg/m3; Type: balk_gen_K80x80x4; Description: ⌄80x80x4; Structural Material: h2_staal_S355; Assembly Code: 28.11.21; Phase Created: 2. nieuwbouw; Staalkwaliteit: S355
Name (NLRS_28_SF_LIB_balk koker vierkant_gen_AT:balk_gen_K80x80x4:...) | In | Length (mm) | OuterSurfaceArea (m2) | GrossVolume (m3) | NetVolume (m3) = Volume (m3) | Massa (kg)
966004 | 03 derde verdieping | 24477.5 | 14.294 | 0.154953 | 0.0285877 | 228.702
966241 | 03 derde verdieping | 24477.5 | 14.294 | 0.154953 | 0.0285877 | 228.702
966251 | 03 derde verdieping | 24477.5 | 14.294 | 0.154953 | 0.0285877 | 228.702
982064 | 03 derde verdieping | 15874.8 | 9.27034 | 0.100494 | 0.0185405 | 148.324
1012647 | 03 derde verdieping | 1726.91 | 1.00845 | 0.010932 | 0.00201688 | 16.1351
1012805 | 03 derde verdieping | 1726.91 | 1.00845 | 0.010932 | 0.00201688 | 16.1351
1012901 | 03 derde verdieping | 1726.91 | 1.00845 | 0.010932 | 0.00201688 | 16.1351
1012902 | 03 derde verdieping | 1726.91 | 1.00845 | 0.010932 | 0.00201688 | 16.1351
1014583 | 01 eerste verdieping | 1820.31 | 1.06299 | 0.0115233 | 0.00212597 | 17.0077
1014983 | 01 eerste verdieping | 1756.63 | 1.02581 | 0.0111202 | 0.0020516 | 16.4128
1015299 | 01 eerste verdieping | 1717.46 | 1.00293 | 0.0108722 | 0.00200585 | 16.0468

# IfcBeam: balk_gen_L150x150x12_tbv bordes (2)
In: 01 eerste verdieping
Classification: 28.11 hoofddraagconstructies; kolommen en liggers, kolom-/liggerconstructies (Uniformat); Material: h2_staal_S235
BaseQuantities - Length: 981.458 mm; CrossSectionArea: 0.00348345 m2; OuterSurfaceArea: 0.575395 m2; GrossVolume: 0.00341886 m3; NetVolume: 0.00341888 m3
Tielemans_Framing_PSET - Soortelijk_gewicht: 8000 kg/m3; Type: balk_gen_L150x150x12_tbv bordes; Description: L150x150x12; Structural Material: h2_staal_S235; Assembly Code: 28.11; Assembly Description: hoofddraagconstructies; kolommen en liggers, kolom-/liggerconstructies; Phase Created: 2. nieuwbouw; Staalkwaliteit: S235; Volume: 0.00341888 m3; Massa: 27.351 kg
Name (NLRS_28_SF_LIB_balk hoeklijn_gen_AT:balk_gen_L150x150x12_tbv bordes:...)
1055745
1056272

# IfcBeam: balk_gen_L70x70x7 (69)
Classification: 28.11.21 (Uniformat); Material: h2_staal_S355
BaseQuantities - CrossSectionArea: 0.000939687 m2
Tielemans_Framing_PSET - Soortelijk_gewicht: 8000 kg/m3; Type: balk_gen_L70x70x7; Description: L70x70x7; Structural Material: h2_staal_S355; Assembly Code: 28.11.21; Phase Created: 2. nieuwbouw; Staalkwaliteit: S355
Name (NLRS_28_SF_LIB_balk hoeklijn_gen_AT:balk_gen_L70x70x7:...) | In | Length (mm) | OuterSurfaceArea (m2) | GrossVolume (m3) | NetVolume (m3) = Volume (m3) | Massa (kg)
967438 | 01 eerste verdieping | 7352.33 | 2.00185 | 0.00690889 | 0.00690891 | 55.2713
968842 | 01 eerste verdieping | 7432.06 | 2.02356 | 0.00698381 | 0.00698384 | 55.8707
968994 | 01 eerste verdieping | 7403.06 | 2.01566 | 0.00695656 | 0.00695659 | 55.6527
969231 | 01 eerste verdieping | 6474.08 | 1.76273 | 0.00608361 | 0.00608364 | 48.6691
969345 | 01 eerste verdieping | 7428.19 | 2.02251 | 0.00698018 | 0.00698021 | 55.8416
969614 | 01 eerste verdieping | 7422.07 | 2.02084 | 0.00697442 | 0.00697445 | 55.7956
969668 | 01 eerste verdieping | 7403.06 | 2.01566 | 0.00695656 | 0.00695659 | 55.6527
969669 | 01 eerste verdieping | 7422.07 | 2.02084 | 0.00697442 | 0.00697445 | 55.7956
969698 | 01 eerste verdieping | 7403.06 | 2.01566 | 0.00695656 | 0.00695659 | 55.6527
969699 | 01 eerste verdieping | 7422.07 | 2.02084 | 0.00697442 | 0.00697445 | 55.7956
969744 | 01 eerste verdieping | 7403.06 | 2.01566 | 0.00695656 | 0.00695659 | 55.6527
969745 | 01 eerste verdieping | 7422.07 | 2.02084 | 0.00697442 | 0.00697445 | 55.7956
969966 | 01 eerste verdieping | 7923.65 | 2.15741 | 0.00744575 | 0.00744578 | 59.5663
969967 | 01 eerste verdieping | 7911.79 | 2.15418 | 0.0074346 | 0.00743463 | 59.4771
970205 | 01 eerste verdieping | 6378.35 | 1.73666 | 0.00599365 | 0.00599367 | 47.9494
970206 | 01 eerste verdieping | 7236.91 | 1.97043 | 0.00680043 | 0.00680046 | 54.4037
970395 | 01 eerste verdieping | 7320.09 | 1.99307 | 0.0068786 | 0.00687863 | 55.029
970396 | 01 eerste verdieping | 7317.71 | 1.99242 | 0.00687636 | 0.00687638 | 55.0111
970833 | 01 eerste verdieping | 7545.59 | 2.05447 | 0.0070905 | 0.00709052 | 56.7242
970834 | 01 eerste verdieping | 7550.22 | 2.05573 | 0.00709485 | 0.00709487 | 56.759
971021 | 01 eerste verdieping | 7412.9 | 2.01834 | 0.00696581 | 0.00696583 | 55.7267
971069 | 01 eerste verdieping | 7426.93 | 2.02216 | 0.00697899 | 0.00697901 | 55.8321
971142 | 01 eerste verdieping | 7347.44 | 2.00052 | 0.0069043 | 0.00690432 | 55.2346
971143 | 01 eerste verdieping | 7426.93 | 2.02216 | 0.00697899 | 0.00697901 | 55.8321
971276 | 01 eerste verdieping | 8534.62 | 2.32376 | 0.00801988 | 0.00801991 | 64.1592
971389 | 01 eerste verdieping | 7590.8 | 2.06678 | 0.00713298 | 0.007133 | 57.064
971461 | 01 eerste verdieping | 8602.57 | 2.34226 | 0.00808372 | 0.00808375 | 64.67
971502 | 01 eerste verdieping | 8594.57 | 2.34008 | 0.00807621 | 0.00807624 | 64.6099
971556 | 01 eerste verdieping | 8602.57 | 2.34226 | 0.00808372 | 0.00808375 | 64.67
971557 | 01 eerste verdieping | 8594.57 | 2.34008 | 0.00807621 | 0.00807624 | 64.6099
971597 | 01 eerste verdieping | 8602.57 | 2.34226 | 0.00808372 | 0.00808375 | 64.67
971598 | 01 eerste verdieping | 8594.57 | 2.34008 | 0.00807621 | 0.00807624 | 64.6099
971641 | 01 eerste verdieping | 8602.57 | 2.34226 | 0.00808372 | 0.00808375 | 64.67
971642 | 01 eerste verdieping | 8594.57 | 2.34008 | 0.00807621 | 0.00807624 | 64.6099
971740 | 01 eerste verdieping | 7565.52 | 2.0599 | 0.00710922 | 0.00710925 | 56.874
971741 | 01 eerste verdieping | 7550.22 | 2.05573 | 0.00709485 | 0.00709487 | 56.759
971742 | 01 eerste verdieping | 7469.62 | 2.03379 | 0.00701911 | 0.00701914 | 56.1531
971743 | 01 eerste verdieping | 7454.58 | 2.02969 | 0.00700497 | 0.007005 | 56.04
972099 | 01 eerste verdieping | 5923.34 | 1.61277 | 0.00556608 | 0.00556611 | 44.5288
972133 | 01 eerste verdieping | 5907.78 | 1.60854 | 0.00555147 | 0.00555149 | 44.4119
972188 | 01 eerste verdieping | 4949.09 | 1.34751 | 0.00465059 | 0.00465061 | 37.2049
972233 | 01 eerste verdieping | 5006.91 | 1.36325 | 0.00470493 | 0.00470495 | 37.6396
972381 | 01 eerste verdieping | 7163.86 | 1.95053 | 0.00673178 | 0.00673181 | 53.8545
972453 | 01 eerste verdieping | 7179.84 | 1.95489 | 0.0067468 | 0.00674683 | 53.9746
972533 | 01 eerste verdieping | 7250.66 | 1.97417 | 0.00681336 | 0.00681338 | 54.5071
972591 | 01 eerste verdieping | 7135.43 | 1.94279 | 0.00670507 | 0.00670509 | 53.6408
982172 | 03 derde verdieping | 6847.39 | 1.86437 | 0.0064344 | 0.00643443 | 51.4754
982204 | 03 derde verdieping | 6847.39 | 1.86437 | 0.0064344 | 0.00643443 | 51.4754
982259 | 03 derde verdieping | 5963.27 | 1.62365 | 0.00560361 | 0.00560363 | 44.8291
982372 | 03 derde verdieping | 5958.29 | 1.62229 | 0.00559893 | 0.00559895 | 44.7916
982518 | 03 derde verdieping | 5963.27 | 1.62365 | 0.00560361 | 0.00560363 | 44.8291
982519 | 03 derde verdieping | 5958.29 | 1.62229 | 0.00559893 | 0.00559895 | 44.7916
982647 | 03 derde verdieping | 6847.39 | 1.86437 | 0.0064344 | 0.00643443 | 51.4754
982648 | 03 derde verdieping | 6847.39 | 1.86437 | 0.0064344 | 0.00643443 | 51.4754
982742 | 03 derde verdieping | 5454.05 | 1.485 | 0.0051251 | 0.00512512 | 41.001
982743 | 03 derde verdieping | 5442.37 | 1.48182 | 0.00511412 | 0.00511414 | 40.9131
982913 | 03 derde verdieping | 5454.05 | 1.485 | 0.0051251 | 0.00512512 | 41.001
982914 | 03 derde verdieping | 5442.37 | 1.48182 | 0.00511412 | 0.00511414 | 40.9131
983025 | 03 derde verdieping | 3054.14 | 0.831564 | 0.00286994 | 0.00286995 | 22.9596
983144 | 03 derde verdieping | 4196.13 | 1.1425 | 0.00394305 | 0.00394307 | 31.5445
983303 | 03 derde verdieping | 4195.67 | 1.14237 | 0.00394262 | 0.00394264 | 31.5411
983304 | 03 derde verdieping | 3059.89 | 0.833129 | 0.00287534 | 0.00287535 | 23.0028
983460 | 03 derde verdieping | 4206.34 | 1.14528 | 0.00395264 | 0.00395266 | 31.6213
983461 | 03 derde verdieping | 3064.82 | 0.834473 | 0.00287998 | 0.00287999 | 23.0399
983634 | 03 derde verdieping | 3093.5 | 0.842281 | 0.00290692 | 0.00290693 | 23.2555
983635 | 03 derde verdieping | 4115.33 | 1.1205 | 0.00386713 | 0.00386714 | 30.9371
1014804 | 01 eerste verdieping | 7786.49 | 2.12006 | 0.00731686 | 0.00731689 | 58.5351
1015140 | 01 eerste verdieping | 6590.34 | 1.79438 | 0.00619286 | 0.00619288 | 49.5431
1015538 | 01 eerste verdieping | 6547.43 | 1.7827 | 0.00615254 | 0.00615256 | 49.2205

# IfcBeam: fund vierkant_gen_1130x1100, NLRS_16_SF_LIB_balk fundering beton_gen_AT:fund vierkant_gen_1130x1100:1032398
In: 00 begane grond
Classification: 16.12 funderingsconstructies; voeten en balken, fundatie balken (Uniformat); Material: f2_beton ihwg_gen
BaseQuantities - CrossSectionArea: 7.8503 m2; NetVolume: 3.10897 m3
Tielemans_Framing_PSET - LoadBearing: yes; Soortelijk_gewicht: 2500 kg/m3; IsExternal: yes; Type: fund vierkant_gen_1130x1100; Description: fund.balk 1130x1100; Structural Material: f2_beton ihwg_gen; Assembly Code: 16.12; Assembly Description: funderingsconstructies; voeten en balken, fundatie balken; Phase Created: 2. nieuwbouw; Sterkteklasse: gen; Volume: 3.10897 m3; Massa: 7772.44 kg

# IfcBeam: fund vierkant_gen_600x600 (16)
In: 00 begane grond
Classification: 16.12 funderingsconstructies; voeten en balken, fundatie balken (Uniformat); Material: f2_beton ihwg_gen
Tielemans_Framing_PSET - LoadBearing: yes; Soortelijk_gewicht: 2500 kg/m3; IsExternal: yes; Type: fund vierkant_gen_600x600; Description: fund.balk 600x600; Structural Material: f2_beton ihwg_gen; Assembly Code: 16.12; Assembly Description: funderingsconstructies; voeten en balken, fundatie balken; Phase Created: 2. nieuwbouw; Sterkteklasse: gen
Name (NLRS_16_SF_LIB_balk fundering beton_gen_AT:fund vierkant_gen_600x600:...) | CrossSectionArea (m2) | NetVolume (m3) = Volume (m3) | Massa (kg)
1021688 | 0.36 | 5.66532 | 14163.3 | BaseQuantities - Length: 15737 mm; OuterSurfaceArea: 37.7688 m2; GrossVolume: 5.66532 m3
1024124 | 0.36 | 2.63196 | 6579.9 | BaseQuantities - Length: 7311 mm; OuterSurfaceArea: 17.5464 m2; GrossVolume: 2.63196 m3
1024223 | 12.8608 | 3.37851 | 8446.27
1024323 | 39.3432 | 8.27496 | 20687.4
1024445 | 15.7825 | 3.1875 | 7968.75
1025817 | 31.9558 | 6.45324 | 16133.1
1027543 | 0.18 | 2.4615 | 6153.75 | BaseQuantities - Length: 13675 mm; OuterSurfaceArea: 24.615 m2; GrossVolume: 2.4615 m3
1028561 | 18.414 | 3.7062 | 9265.5
1032376 | 0.36 | 3.30244 | 8256.11 | BaseQuantities - Length: 9340.3 mm; OuterSurfaceArea: 22.4167 m2; GrossVolume: 3.36251 m3
1032865 | 10.2832 | 2.89294 | 7232.36
1034048 | 12.4408 | 3.34251 | 8356.27
1034223 | 8.30084 | 2.10051 | 5251.27
1034423 | 5.33202 | 1.43989 | 3599.73
1034542 | 0.36 | 0.789948 | 1974.87 | BaseQuantities - Length: 2194.3 mm; OuterSurfaceArea: 5.26632 m2; GrossVolume: 0.789948 m3
1034817 | 0.36 | 0.68652 | 1716.3 | BaseQuantities - Length: 1907 mm; OuterSurfaceArea: 4.5768 m2; GrossVolume: 0.68652 m3
1038276 | 2.878 | 0.68424 | 1710.6

# IfcBeam: fund vierkant_gen_600x600 (4)
In: 00 begane grond
Type - PredefinedType: BEAM; Material: f2_beton ihwg_gen
Classification: 16.12 funderingsconstructies; voeten en balken, fundatie balken (Uniformat)
Tielemans_Framing_PSET - LoadBearing: yes; Soortelijk_gewicht: 2500 kg/m3; IsExternal: yes; Type: fund vierkant_gen_600x600; Description: fund.balk 600x600; Structural Material: f2_beton ihwg_gen; Assembly Code: 16.12; Assembly Description: funderingsconstructies; voeten en balken, fundatie balken; Phase Created: 2. nieuwbouw; Sterkteklasse: gen
BaseQuantities - Height: 600 mm; Width: 600 mm; CrossSectionArea: 0.36 m2
Name (NLRS_16_SF_LIB_balk fundering beton_gen_AT:fund vierkant_gen_600x600:...) | Volume (m3) = NetVolume (m3) | Massa (kg) | Length (mm) | OuterSurfaceArea (m2) | GrossSurfaceArea (m2) | GrossVolume (m3)
1022303 | 7.24896 | 18122.4 | 30036 | 6.432 | 7.152 | 0.9648
1022690 | 3.798 | 9495 | 24350 | 8.6856 | 9.4056 | 1.30284
1023036 | 6.03376 | 15084.4 | 26244.2 | 8.1 | 8.82 | 1.215
1023900 | 5.3828 | 13457 | 22026.1 | 8.1 | 8.82 | 1.215

# IfcBeam: fund vierkant_gen_700x600 (13)
In: 00 begane grond
Classification: 16.12 funderingsconstructies; voeten en balken, fundatie balken (Uniformat); Material: f2_beton ihwg_gen
Tielemans_Framing_PSET - LoadBearing: yes; Soortelijk_gewicht: 2500 kg/m3; IsExternal: yes; Type: fund vierkant_gen_700x600; Description: fund.balk 700x600; Structural Material: f2_beton ihwg_gen; Assembly Code: 16.12; Assembly Description: funderingsconstructies; voeten en balken, fundatie balken; Phase Created: 2. nieuwbouw; Sterkteklasse: gen
Name (NLRS_16_SF_LIB_balk fundering beton_gen_AT:fund vierkant_gen_700x600:...) | CrossSectionArea (m2) | NetVolume (m3) = Volume (m3) | Massa (kg) | Length (mm) | OuterSurfaceArea (m2) | GrossVolume (m3)
1018052 | 2.49788 | 0.670525 | 1676.31
1018063 | 2.69099 | 0.733731 | 1834.33
1019215 | 0.42 | 12.2925 | 30731.2 | 29684.9 | 77.1808 | 12.4677
1019458 | 0.42 | 9.62999 | 24075 | 23345.7 | 60.6987 | 9.80518
1019775 | 0.42 | 11.4678 | 28669.6 | 27336.8 | 71.0758 | 11.4815
1019883 | 2.52182 | 0.679483 | 1698.71
1020137 | 2.49788 | 0.670525 | 1676.31
1020666 | 0.42 | 11.382 | 28455 | 27100 | 70.46 | 11.382
1020798 | 0.42 | 5.39704 | 13492.6 | 13061.2 | 33.9592 | 5.48572
1020971 | 2.69093 | 0.733712 | 1834.28
1021099 | 0.42 | 2.64163 | 6604.08 | 6345.48 | 16.4982 | 2.6651
1021308 | 0.42 | 4.68324 | 11708.1 | 11321.1 | 29.4349 | 4.75487
1021503 | 0.42 | 2.67721 | 6693.03 | 6489 | 16.8714 | 2.72538

# IfcBeam: fund vierkant_gen_700x600, NLRS_16_SF_LIB_balk fundering beton_gen_AT:fund vierkant_gen_700x600:1019958
In: 00 begane grond
Type - PredefinedType: BEAM; Material: f2_beton ihwg_gen
Classification: 16.12 funderingsconstructies; voeten en balken, fundatie balken (Uniformat)
Tielemans_Framing_PSET - LoadBearing: yes; Soortelijk_gewicht: 2500 kg/m3; IsExternal: yes; Type: fund vierkant_gen_700x600; Description: fund.balk 700x600; Structural Material: f2_beton ihwg_gen; Assembly Code: 16.12; Assembly Description: funderingsconstructies; voeten en balken, fundatie balken; Phase Created: 2. nieuwbouw; Sterkteklasse: gen; Volume: 6.10113 m3; Massa: 15252.8 kg
BaseQuantities - Length: 23176.5 mm; Height: 600 mm; Width: 700 mm; CrossSectionArea: 21.1944 m2; NetVolume: 6.10113 m3

# IfcBeam: fund vierkant_gen_800x600 (9)
In: 00 begane grond
Classification: 16.12 funderingsconstructies; voeten en balken, fundatie balken (Uniformat); Material: f2_beton ihwg_gen
Tielemans_Framing_PSET - Soortelijk_gewicht: 2500 kg/m3; Type: fund vierkant_gen_800x600; Description: fund.balk 800x600; Structural Material: f2_beton ihwg_gen; Assembly Code: 16.12; Assembly Description: funderingsconstructies; voeten en balken, fundatie balken; IsExternal: yes; Phase Created: 2. nieuwbouw; Sterkteklasse: gen
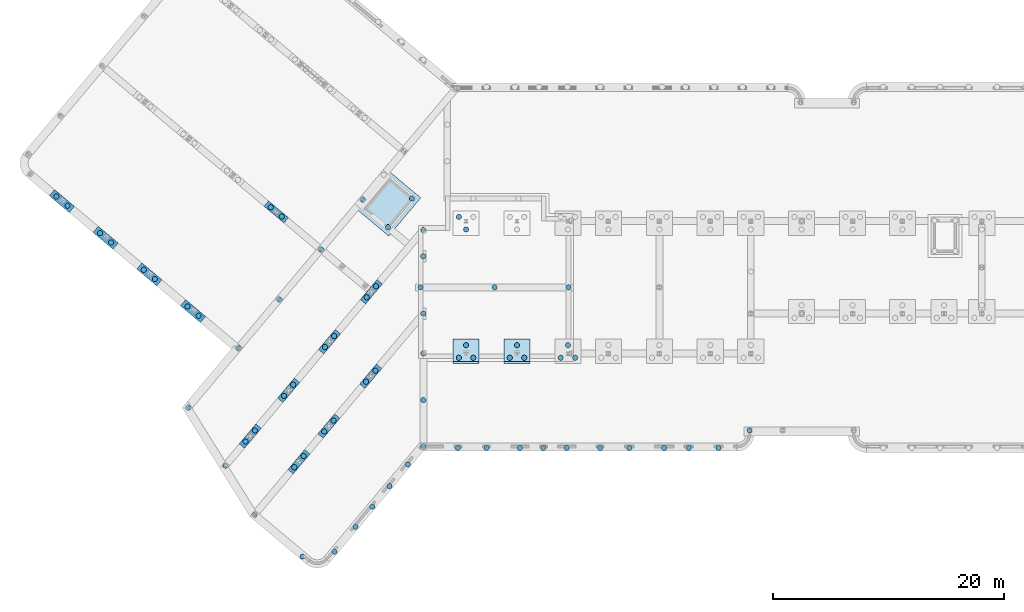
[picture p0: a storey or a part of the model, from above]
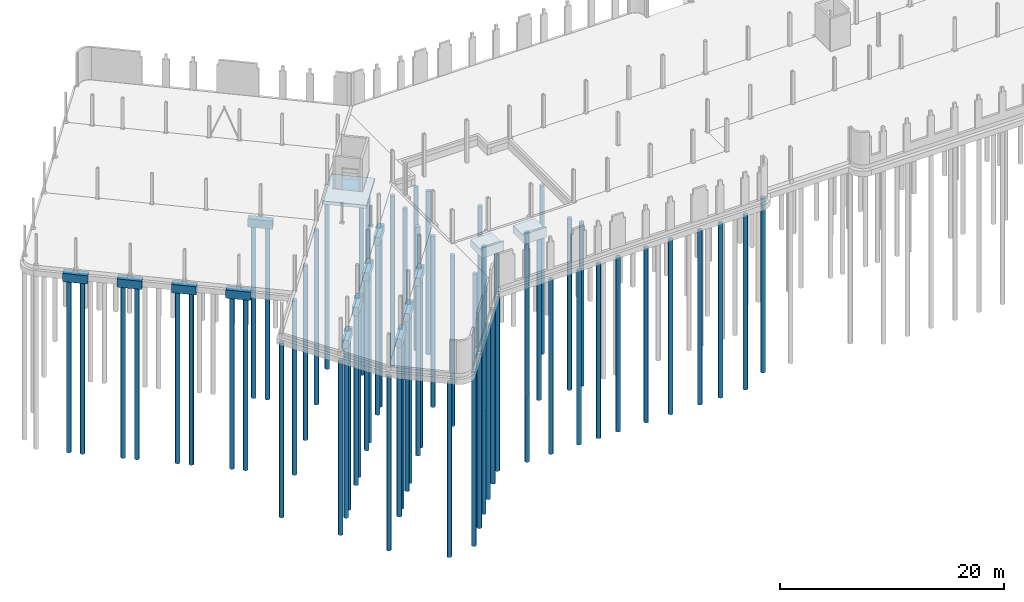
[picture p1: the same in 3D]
Properties of the parts of a building model (IFC2X3), part 2 of 3

# IfcBeam: fund vierkant_gen_800x600 (9)
Name (NLRS_16_SF_LIB_balk fundering beton_gen_AT:fund vierkant_gen_800x600:...) | Length (mm) | CrossSectionArea (m2) | OuterSurfaceArea (m2) | GrossVolume (m3) | NetVolume (m3) = Volume (m3) | Massa (kg)
1016345 | 27500 | 0.48 | 77 | 13.2 | 13.2 | 33000
1017933 |  | 3.08844 |  |  | 0.894281 | 2235.7
1018032 |  | 3.08844 |  |  | 0.894281 | 2235.7
1018042 |  | 2.83004 |  |  | 0.804577 | 2011.44
1018166 |  | 2.83004 |  |  | 0.804577 | 2011.44
1018239 | 28800 | 0.48 | 80.64 | 13.824 | 13.824 | 34560
1018527 | 27500 | 0.48 | 77 | 13.2 | 13.2 | 33000
1018673 | 5603 | 0.48 | 15.6884 | 2.68944 | 2.68944 | 6723.6
1020252 | 10003 | 0.48 | 28.0084 | 4.80144 | 4.80144 | 12003.6

# IfcBeam: staaf_gen_ø16 (15)
Classification: 28.11 hoofddraagconstructies; kolommen en liggers, kolom-/liggerconstructies (Uniformat); Material: h2_staal_S355
BaseQuantities - CrossSectionArea: 0.000200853 m2
Tielemans_Framing_PSET - Soortelijk_gewicht: 8000 kg/m3; Type: staaf_gen_ø16; Description: ø16; Structural Material: h2_staal_S355; Assembly Code: 28.11; Assembly Description: hoofddraagconstructies; kolommen en liggers, kolom-/liggerconstructies; Phase Created: 2. nieuwbouw; Staalkwaliteit: S355
Name (NLRS_28_SF_LIB_balk staaf_gen_AT:staaf_gen_ø16:...) | In | Length (mm) | OuterSurfaceArea (m2) | GrossVolume (m3) | NetVolume (m3) = Volume (m3) | Massa (kg)
884609 | 01 eerste verdieping | 6621.83 | 0.33285 | 0.00133002 | 0.00133092 | 10.6474
884610 | 01 eerste verdieping | 6519.29 | 0.327695 | 0.00130942 | 0.00131031 | 10.4825
884669 | 01 eerste verdieping | 6621.83 | 0.33285 | 0.00133002 | 0.00133092 | 10.6474
884670 | 01 eerste verdieping | 6519.29 | 0.327695 | 0.00130942 | 0.00131031 | 10.4825
888632 | 01 eerste verdieping | 3442.25 | 0.173026 | 0.000691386 | 0.000691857 | 5.53486
889384 | 01 eerste verdieping | 3442.25 | 0.173026 | 0.000691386 | 0.000691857 | 5.53486
934446 | 03 derde verdieping | 6780.42 | 0.340821 | 0.00136187 | 0.0013628 | 10.9024
934447 | 03 derde verdieping | 928.798 | 0.0466865 | 0.000186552 | 0.000186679 | 1.49343
934554 | 03 derde verdieping | 6999.87 | 0.351852 | 0.00140595 | 0.0014069 | 11.2552
934555 | 03 derde verdieping | 6519.29 | 0.327695 | 0.00130942 | 0.00131031 | 10.4825
945802 | 01 eerste verdieping | 6838.94 | 0.343763 | 0.00137362 | 0.00137456 | 10.9965
945803 | 01 eerste verdieping | 6829.26 | 0.343276 | 0.00137168 | 0.00137261 | 10.9809
949994 | 01 eerste verdieping | 6838.94 | 0.343763 | 0.00137362 | 0.00137456 | 10.9965
949995 | 01 eerste verdieping | 6829.26 | 0.343276 | 0.00137168 | 0.00137261 | 10.9809
966479 | 03 derde verdieping | 5944.32 | 0.298794 | 0.00119394 | 0.00119475 | 9.558

# IfcColumn: kolom_gen_HEA180 (31)
Type - PredefinedType: COLUMN; Material: h2_staal_S355
Classification: 28.11.21 (Uniformat)
BaseQuantities - CrossSectionArea: 0.00452527 m2
Tielemans_Column_PSET - Soortelijk_gewicht: 8000 kg/m3; Type: kolom_gen_HEA180; Description: kol. HEA180; Structural Material: h2_staal_S355; Assembly Code: 28.11.21; Phase Created: 2. nieuwbouw; Staalkwaliteit: S355
Name (NLRS_28_SC_TLB_kolom HEA_gen_AT:kolom_gen_HEA180:...) | In | Length (mm) | OuterSurfaceArea (m2) | GrossVolume (m3) | NetVolume (m3) = Volume (m3) | Massa (kg)
873165 | 00 begane grond | 2164 | 2.21647 | 0.00979269 | 0.00979247 | 78.3397
873389 | 00 begane grond | 2164 | 2.21647 | 0.00979269 | 0.00979247 | 78.3397
932494 | 02 tweede verdieping | 3873 | 3.96691 | 0.0175264 | 0.017526 | 140.208
932495 | 02 tweede verdieping | 3873 | 3.96691 | 0.0175264 | 0.017526 | 140.208
932496 | 02 tweede verdieping | 3873 | 3.96691 | 0.0175264 | 0.017526 | 140.208
932497 | 02 tweede verdieping | 3873 | 3.96691 | 0.0175264 | 0.017526 | 140.208
932704 | 02 tweede verdieping | 3604.33 | 3.69173 | 0.0163106 | 0.0163102 | 130.482
932978 | 02 tweede verdieping | 3873 | 3.96691 | 0.0175264 | 0.017526 | 140.208
935751 | 02 tweede verdieping | 3702 | 3.79177 | 0.0167526 | 0.0167522 | 134.017
935767 | 02 tweede verdieping | 3873 | 3.96691 | 0.0175264 | 0.017526 | 140.208
935834 | 02 tweede verdieping | 3985 | 4.08163 | 0.0180332 | 0.0180328 | 144.262
935835 | 02 tweede verdieping | 3780 | 3.87166 | 0.0171055 | 0.0171051 | 136.841
935836 | 02 tweede verdieping | 3985 | 4.08163 | 0.0180332 | 0.0180328 | 144.262
953428 | 02 tweede verdieping | 3893 | 3.9874 | 0.0176169 | 0.0176165 | 140.932
959792 | 02 tweede verdieping | 3985 | 4.08163 | 0.0180332 | 0.0180328 | 144.262
959905 | 02 tweede verdieping | 3814.42 | 3.90691 | 0.0172613 | 0.0172609 | 138.087
959966 | 02 tweede verdieping | 3873 | 3.96691 | 0.0175264 | 0.017526 | 140.208
960044 | 02 tweede verdieping | 3992.42 | 4.08923 | 0.0180668 | 0.0180664 | 144.531
976249 | 02 tweede verdieping | 4165 | 4.26599 | 0.0188478 | 0.0188473 | 150.779
976250 | 02 tweede verdieping | 4165 | 4.26599 | 0.0188478 | 0.0188473 | 150.779
976251 | 02 tweede verdieping | 4165 | 4.26599 | 0.0188478 | 0.0188473 | 150.779
976252 | 02 tweede verdieping | 4165 | 4.26599 | 0.0188478 | 0.0188473 | 150.779
976253 | 02 tweede verdieping | 4165 | 4.26599 | 0.0188478 | 0.0188473 | 150.779
976254 | 02 tweede verdieping | 4165 | 4.26599 | 0.0188478 | 0.0188473 | 150.779
976255 | 02 tweede verdieping | 4165 | 4.26599 | 0.0188478 | 0.0188473 | 150.779
976256 | 02 tweede verdieping | 4165 | 4.26599 | 0.0188478 | 0.0188473 | 150.779
976430 | 02 tweede verdieping | 4165 | 4.26599 | 0.0188478 | 0.0188473 | 150.779
976852 | 02 tweede verdieping | 4165 | 4.26599 | 0.0188478 | 0.0188473 | 150.779
976990 | 02 tweede verdieping | 4165 | 4.26599 | 0.0188478 | 0.0188473 | 150.779
976991 | 02 tweede verdieping | 4165 | 4.26599 | 0.0188478 | 0.0188473 | 150.779
1014388 | 02 tweede verdieping | 3745 | 3.83581 | 0.0169471 | 0.0169468 | 135.574

# IfcColumn: kolom_gen_HEA200 (37)
Type - PredefinedType: COLUMN; Material: h2_staal_S355
Classification: 28.11.21 (Uniformat)
Tielemans_Column_PSET - Soortelijk_gewicht: 8000 kg/m3; Type: kolom_gen_HEA200; Description: kol. HEA200; Structural Material: h2_staal_S355; Assembly Code: 28.11.21; Phase Created: 2. nieuwbouw; Staalkwaliteit: S355
Name (NLRS_28_SC_TLB_kolom HEA_gen_AT:kolom_gen_HEA200:...) | In | Length (mm) | CrossSectionArea (m2) | OuterSurfaceArea (m2) | GrossVolume (m3) | NetVolume (m3) = Volume (m3) | Massa (kg)
852135 | 00 begane grond | 3308 | 0.00538331 | 3.75821 | 0.017808 | 0.0178075 | 142.46
852219 | 00 begane grond | 3308 | 0.00538331 | 3.75821 | 0.017808 | 0.0178075 | 142.46
852237 | 00 begane grond | 3308 | 0.00538331 | 3.75821 | 0.017808 | 0.0178075 | 142.46
852249 | 00 begane grond | 3308 | 0.00538331 | 3.75821 | 0.017808 | 0.0178075 | 142.46
852585 | 00 begane grond | 3308 | 0.00538331 | 3.75821 | 0.017808 | 0.0178075 | 142.46
858326 | 00 begane grond | 3308 | 0.00538331 | 3.75821 | 0.017808 | 0.0178075 | 142.46
858433 | 00 begane grond | 3308 | 0.00538331 | 3.75821 | 0.017808 | 0.0178075 | 142.46
858486 | 00 begane grond | 3308 | 0.00538331 | 3.75821 | 0.017808 | 0.0178075 | 142.46
858583 | 00 begane grond | 3308 | 0.00538331 | 3.75821 | 0.017808 | 0.0178075 | 142.46
858656 | 00 begane grond | 3308 | 0.00538331 | 3.75821 | 0.017808 | 0.0178075 | 142.46
859817 | 00 begane grond | 3529 | 0.00538331 | 4.00929 | 0.0189977 | 0.0189972 | 151.978
911183 | 01 eerste verdieping | 8260 | 0.00538331 | 9.38416 | 0.0444661 | 0.0444649 | 355.72
911184 | 01 eerste verdieping | 8260 | 0.00538331 | 9.38416 | 0.0444661 | 0.0444649 | 355.72
911185 | 01 eerste verdieping | 8260 | 0.00538331 | 9.38416 | 0.0444661 | 0.0444649 | 355.72
911186 | 01 eerste verdieping | 8450 | 0.00538331 | 9.60002 | 0.045489 | 0.0454877 | 363.902
911187 | 01 eerste verdieping | 8291.9 | 0.00538331 | 9.42041 | 0.0446379 | 0.0446367 | 357.093
911188 | 01 eerste verdieping | 8440.9 | 0.00538331 | 9.58968 | 0.04544 | 0.0454388 | 363.51
911189 | 01 eerste verdieping | 3765 | 0.00538331 | 4.27741 | 0.0202682 | 0.0202676 | 162.141
911193 | 01 eerste verdieping | 3904.9 | 0.00538331 | 4.43635 | 0.0210213 | 0.0210207 | 168.166
911256 | 01 eerste verdieping | 8260 | 0.00538331 | 9.38416 | 0.0444661 | 0.0444649 | 355.72
911257 | 01 eerste verdieping | 8260 | 0.00538331 | 9.38416 | 0.0444661 | 0.0444649 | 355.72
911509 | 01 eerste verdieping | 8336.38 | 0.00538331 | 9.47094 | 0.0448773 | 0.0448761 | 359.009
911637 | 01 eerste verdieping | 3740 | 0.00538331 | 4.249 | 0.0201336 | 0.020133 | 161.064
911638 | 01 eerste verdieping | 3740 | 0.00538331 | 4.249 | 0.0201336 | 0.020133 | 161.064
911639 | 01 eerste verdieping | 3740 | 0.00538331 | 4.249 | 0.0201336 | 0.020133 | 161.064
911640 | 01 eerste verdieping | 3740 | 0.00538331 | 4.249 | 0.0201336 | 0.020133 | 161.064
911641 | 01 eerste verdieping | 3755 | 0.00538331 | 4.26605 | 0.0202143 | 0.0202138 | 161.71
929222 | 02 tweede verdieping | 4185 | 0.00538331 | 4.75457 | 0.0225292 | 0.0225285 | 180.228
929223 | 02 tweede verdieping | 4245 | 0.00538331 | 4.82273 | 0.0228522 | 0.0228515 | 182.812
929225 | 02 tweede verdieping | 4245 | 0.00538331 | 4.82273 | 0.0228522 | 0.0228515 | 182.812
929226 | 02 tweede verdieping | 4245 | 0.00538331 | 4.82273 | 0.0228522 | 0.0228515 | 182.812
929227 | 02 tweede verdieping | 4245 | 0.00538331 | 4.82273 | 0.0228522 | 0.0228515 | 182.812
931570 | 02 tweede verdieping | 4005 | 0.00538331 | 4.55007 | 0.0215602 | 0.0215596 | 172.477
934248 | 02 tweede verdieping |  |  |  |  | 0.0234436 | 187.549 | BaseQuantities - GrossSurfaceArea: 0 m2
934250 | 02 tweede verdieping | 4092.38 | 0.00538331 | 4.64934 | 0.0220305 | 0.0220299 | 176.24
934323 | 02 tweede verdieping | 4102.38 | 0.00538331 | 4.6607 | 0.0220844 | 0.0220838 | 176.67
1072522 | 02 tweede verdieping | 4266.9 | 0.00538331 | 4.84761 | 0.02297 | 0.0229694 | 183.755

# IfcColumn: kolom_gen_HEA240 (57)
Type - PredefinedType: COLUMN; Material: h2_staal_S355
Classification: 28.11.21 (Uniformat)
BaseQuantities - CrossSectionArea: 0.00768381 m2
Tielemans_Column_PSET - Soortelijk_gewicht: 8000 kg/m3; Type: kolom_gen_HEA240; Description: kol. HEA240; Structural Material: h2_staal_S355; Assembly Code: 28.11.21; Phase Created: 2. nieuwbouw; Staalkwaliteit: S355
Name (NLRS_28_SC_TLB_kolom HEA_gen_AT:kolom_gen_HEA240:...) | In | Length (mm) | OuterSurfaceArea (m2) | GrossVolume (m3) | NetVolume (m3) = Volume (m3) | Massa (kg)
852345 | 00 begane grond | 3308 | 4.52848 | 0.0254181 | 0.0254174 | 203.339
854763 | 00 begane grond | 3308 | 4.52848 | 0.0254181 | 0.0254174 | 203.339
854812 | 00 begane grond | 3308 | 4.52848 | 0.0254181 | 0.0254174 | 203.339
854962 | 00 begane grond | 3308 | 4.52848 | 0.0254181 | 0.0254174 | 203.339
854972 | 00 begane grond | 3308 | 4.52848 | 0.0254181 | 0.0254174 | 203.339
855061 | 00 begane grond | 3308 | 4.52848 | 0.0254181 | 0.0254174 | 203.339
858288 | 00 begane grond | 3308 | 4.52848 | 0.0254181 | 0.0254174 | 203.339
858298 | 00 begane grond | 3308 | 4.52848 | 0.0254181 | 0.0254174 | 203.339
858310 | 00 begane grond | 3308 | 4.52848 | 0.0254181 | 0.0254174 | 203.339
900457 | 01 eerste verdieping | 3579 | 4.89946 | 0.0275004 | 0.0274997 | 219.997
900458 | 01 eerste verdieping | 3579 | 4.89946 | 0.0275004 | 0.0274997 | 219.997
900460 | 01 eerste verdieping | 3579 | 4.89946 | 0.0275004 | 0.0274997 | 219.997
900461 | 01 eerste verdieping | 3579 | 4.89946 | 0.0275004 | 0.0274997 | 219.997
900463 | 01 eerste verdieping | 3579 | 4.89946 | 0.0275004 | 0.0274997 | 219.997
900464 | 01 eerste verdieping | 3579 | 4.89946 | 0.0275004 | 0.0274997 | 219.997
900465 | 01 eerste verdieping | 3579 | 4.89946 | 0.0275004 | 0.0274997 | 219.997
900466 | 01 eerste verdieping | 3579 | 4.89946 | 0.0275004 | 0.0274997 | 219.997
900467 | 01 eerste verdieping | 3579 | 4.89946 | 0.0275004 | 0.0274997 | 219.997
900468 | 01 eerste verdieping | 3579 | 4.89946 | 0.0275004 | 0.0274997 | 219.997
900469 | 01 eerste verdieping | 3579 | 4.89946 | 0.0275004 | 0.0274997 | 219.997
900470 | 01 eerste verdieping | 3579 | 4.89946 | 0.0275004 | 0.0274997 | 219.997
900471 | 01 eerste verdieping | 3579 | 4.89946 | 0.0275004 | 0.0274997 | 219.997
900473 | 01 eerste verdieping | 3579 | 4.89946 | 0.0275004 | 0.0274997 | 219.997
900474 | 01 eerste verdieping | 3579 | 4.89946 | 0.0275004 | 0.0274997 | 219.997
900476 | 01 eerste verdieping | 3579 | 4.89946 | 0.0275004 | 0.0274997 | 219.997
900477 | 01 eerste verdieping | 3579 | 4.89946 | 0.0275004 | 0.0274997 | 219.997
900478 | 01 eerste verdieping | 3579 | 4.89946 | 0.0275004 | 0.0274997 | 219.997
900479 | 01 eerste verdieping | 3579 | 4.89946 | 0.0275004 | 0.0274997 | 219.997
900480 | 01 eerste verdieping | 3579 | 4.89946 | 0.0275004 | 0.0274997 | 219.997
900481 | 01 eerste verdieping | 3579 | 4.89946 | 0.0275004 | 0.0274997 | 219.997
900482 | 01 eerste verdieping | 3579 | 4.89946 | 0.0275004 | 0.0274997 | 219.997
900484 | 01 eerste verdieping | 3579 | 4.89946 | 0.0275004 | 0.0274997 | 219.997
900485 | 01 eerste verdieping | 3579 | 4.89946 | 0.0275004 | 0.0274997 | 219.997
900487 | 01 eerste verdieping | 3579 | 4.89946 | 0.0275004 | 0.0274997 | 219.997
900488 | 01 eerste verdieping | 3579 | 4.89946 | 0.0275004 | 0.0274997 | 219.997
900489 | 01 eerste verdieping | 3579 | 4.89946 | 0.0275004 | 0.0274997 | 219.997
900490 | 01 eerste verdieping | 3579 | 4.89946 | 0.0275004 | 0.0274997 | 219.997
900491 | 01 eerste verdieping | 3544 | 4.85155 | 0.0272314 | 0.0272307 | 217.846
900492 | 01 eerste verdieping | 3579 | 4.89946 | 0.0275004 | 0.0274997 | 219.997
900499 | 01 eerste verdieping | 3579 | 4.89946 | 0.0275004 | 0.0274997 | 219.997
902616 | 01 eerste verdieping | 3519 | 4.81732 | 0.0270393 | 0.0270386 | 216.309
902617 | 01 eerste verdieping | 3519 | 4.81732 | 0.0270393 | 0.0270386 | 216.309
902618 | 01 eerste verdieping | 3529 | 4.83101 | 0.0271162 | 0.0271155 | 216.924
902619 | 01 eerste verdieping | 3519 | 4.81732 | 0.0270393 | 0.0270386 | 216.309
902622 | 01 eerste verdieping | 3529 | 4.83101 | 0.0271162 | 0.0271155 | 216.924
902623 | 01 eerste verdieping | 3529 | 4.83101 | 0.0271162 | 0.0271155 | 216.924
902626 | 01 eerste verdieping | 3519 | 4.81732 | 0.0270393 | 0.0270386 | 216.309
909020 | 01 eerste verdieping | 3554 | 4.86524 | 0.0273083 | 0.0273076 | 218.46
909021 | 01 eerste verdieping | 3745 | 5.12671 | 0.0287759 | 0.0287751 | 230.201
909022 | 01 eerste verdieping | 3745 | 5.12671 | 0.0287759 | 0.0287751 | 230.201
909025 | 01 eerste verdieping | 3745 | 5.12671 | 0.0287759 | 0.0287751 | 230.201
909026 | 01 eerste verdieping | 3534 | 4.83786 | 0.0271546 | 0.0271539 | 217.231
936368 | 00 begane grond | 3308 | 4.52848 | 0.0254181 | 0.0254174 | 203.339
948351 | 01 eerste verdieping | 3579 | 4.89946 | 0.0275004 | 0.0274997 | 219.997
948665 | 01 eerste verdieping | 3529 | 4.83101 | 0.0271162 | 0.0271155 | 216.924
950680 | 01 eerste verdieping | 3579 | 4.89946 | 0.0275004 | 0.0274997 | 219.997
1001639 | 01 eerste verdieping | 3529 | 4.83101 | 0.0271162 | 0.0271155 | 216.924

# IfcColumn: kolom_gen_HEA280 (49)
In: 00 begane grond
Type - PredefinedType: COLUMN; Material: h2_staal_S355
Classification: 28.11.21 (Uniformat)
BaseQuantities - CrossSectionArea: 0.00972678 m2
Tielemans_Column_PSET - Soortelijk_gewicht: 8000 kg/m3; Type: kolom_gen_HEA280; Description: kol. HEA280; Structural Material: h2_staal_S355; Assembly Code: 28.11.21; Phase Created: 2. nieuwbouw; Staalkwaliteit: S355
Name (NLRS_28_SC_TLB_kolom HEA_gen_AT:kolom_gen_HEA280:...) | Length (mm) | OuterSurfaceArea (m2) | GrossVolume (m3) | NetVolume (m3) = Volume (m3) | Massa (kg)
837283 | 3529 | 5.65627 | 0.0343258 | 0.0343249 | 274.599
837620 | 3529 | 5.65627 | 0.0343258 | 0.0343249 | 274.599
837652 | 3529 | 5.65627 | 0.0343258 | 0.0343249 | 274.599
837838 | 3529 | 5.65627 | 0.0343258 | 0.0343249 | 274.599
837858 | 3529 | 5.65627 | 0.0343258 | 0.0343249 | 274.599
837868 | 3529 | 5.65627 | 0.0343258 | 0.0343249 | 274.599
837878 | 3529 | 5.65627 | 0.0343258 | 0.0343249 | 274.599
837894 | 3529 | 5.65627 | 0.0343258 | 0.0343249 | 274.599
837906 | 3529 | 5.65627 | 0.0343258 | 0.0343249 | 274.599
837918 | 4633 | 7.42576 | 0.0450642 | 0.0450629 | 360.504
837932 | 4633 | 7.42576 | 0.0450642 | 0.0450629 | 360.504
838270 | 3529 | 5.65627 | 0.0343258 | 0.0343249 | 274.599
838271 | 3529 | 5.65627 | 0.0343258 | 0.0343249 | 274.599
838274 | 3529 | 5.65627 | 0.0343258 | 0.0343249 | 274.599
838275 | 3529 | 5.65627 | 0.0343258 | 0.0343249 | 274.599
838277 | 3529 | 5.65627 | 0.0343258 | 0.0343249 | 274.599
838278 | 3529 | 5.65627 | 0.0343258 | 0.0343249 | 274.599
838279 | 3529 | 5.65627 | 0.0343258 | 0.0343249 | 274.599
838280 | 3529 | 5.65627 | 0.0343258 | 0.0343249 | 274.599
838281 | 3529 | 5.65627 | 0.0343258 | 0.0343249 | 274.599
838282 | 3529 | 5.65627 | 0.0343258 | 0.0343249 | 274.599
838283 | 3529 | 5.65627 | 0.0343258 | 0.0343249 | 274.599
838423 | 3529 | 5.65627 | 0.0343258 | 0.0343249 | 274.599
838468 | 3524 | 5.64825 | 0.0342772 | 0.0342762 | 274.21
838478 | 3524 | 5.64825 | 0.0342772 | 0.0342762 | 274.21
838861 | 3529 | 5.65627 | 0.0343258 | 0.0343249 | 274.599
842340 | 3529 | 5.65627 | 0.0343258 | 0.0343249 | 274.599
843326 | 3529 | 5.65627 | 0.0343258 | 0.0343249 | 274.599
843461 | 3529 | 5.65627 | 0.0343258 | 0.0343249 | 274.599
843640 | 3529 | 5.65627 | 0.0343258 | 0.0343249 | 274.599
843706 | 3529 | 5.65627 | 0.0343258 | 0.0343249 | 274.599
843950 | 3544 | 5.68031 | 0.0344717 | 0.0344708 | 275.766
844693 | 3524 | 5.64825 | 0.0342772 | 0.0342762 | 274.21
845749 | 3529 | 5.65627 | 0.0343258 | 0.0343249 | 274.599
845759 | 3529 | 5.65627 | 0.0343258 | 0.0343249 | 274.599
846425 | 3404 | 5.45592 | 0.03311 | 0.0331091 | 264.872
846538 | 3864 | 6.19321 | 0.0375843 | 0.0375833 | 300.666
846682 | 3308 | 5.30205 | 0.0321762 | 0.0321753 | 257.403
847103 | 3308 | 5.30205 | 0.0321762 | 0.0321753 | 257.403
848260 | 3308 | 5.30205 | 0.0321762 | 0.0321753 | 257.403
848274 | 3864 | 6.19321 | 0.0375843 | 0.0375833 | 300.666
848344 | 3524 | 5.64825 | 0.0342772 | 0.0342762 | 274.21
861036 | 3529 | 5.65627 | 0.0343258 | 0.0343249 | 274.599
871423 | 3544 | 5.68031 | 0.0344717 | 0.0344708 | 275.766
878428 | 3524 | 5.64825 | 0.0342772 | 0.0342762 | 274.21
946474 | 3529 | 5.65627 | 0.0343258 | 0.0343249 | 274.599
948720 | 3529 | 5.65627 | 0.0343258 | 0.0343249 | 274.599
948733 | 3529 | 5.65627 | 0.0343258 | 0.0343249 | 274.599
950679 | 3529 | 5.65627 | 0.0343258 | 0.0343249 | 274.599

# IfcColumn: kolom_gen_UNP240, NLRS_28_SC_TLB_kolom UNP_gen_AT:kolom_gen_UNP240:944717
In: 01 eerste verdieping
Type - PredefinedType: COLUMN; Material: h2_staal_S355
Classification: 28.11.21 (Uniformat)
BaseQuantities - Length: 2374.97 mm; CrossSectionArea: 0.00401297 m2; OuterSurfaceArea: 1.82527 m2; GrossVolume: 0.00953067 m3; NetVolume: 0.00953052 m3
Tielemans_Column_PSET - Soortelijk_gewicht: 8000 kg/m3; Type: kolom_gen_UNP240; Description: kol. UNP240; Structural Material: h2_staal_S355; Assembly Code: 28.11.21; Phase Created: 2. nieuwbouw; Staalkwaliteit: S355; Volume: 0.00953052 m3; Massa: 76.2442 kg

# IfcColumn: kolom_gen_ø273x8 (10)
In: 01 eerste verdieping
Type - PredefinedType: COLUMN; Material: h2_staal_S355
Classification: 28.11.21 (Uniformat)
BaseQuantities - CrossSectionArea: 0.0585271 m2
Tielemans_Column_PSET - Soortelijk_gewicht: 8000 kg/m3; Type: kolom_gen_ø273x8; Description: kol. ø273x8; Structural Material: h2_staal_S355; Assembly Code: 28.11.21; Phase Created: 2. nieuwbouw; Staalkwaliteit: S355
Name (NLRS_28_SC_TLB_kolom buis_gen_AT:kolom_gen_ø273x8:...) | Length (mm) | OuterSurfaceArea (m2) | GrossVolume (m3) | NetVolume (m3) = Volume (m3) | Massa (kg)
900459 | 3579 | 5.95919 | 0.209469 | 0.0238356 | 190.685
900462 | 3579 | 5.95919 | 0.209469 | 0.0238356 | 190.685
900472 | 3579 | 5.95919 | 0.209469 | 0.0238356 | 190.685
900475 | 3579 | 5.95919 | 0.209469 | 0.0238356 | 190.685
902620 | 3529 | 5.87594 | 0.206542 | 0.0235026 | 188.021
902621 | 3529 | 5.87594 | 0.206542 | 0.0235026 | 188.021
936077 | 3529 | 5.87594 | 0.206542 | 0.0235026 | 188.021
1001637 | 3529 | 5.87594 | 0.206542 | 0.0235026 | 188.021
1001638 | 3529 | 5.87594 | 0.206542 | 0.0235026 | 188.021
1041945 | 3529 | 5.87594 | 0.206542 | 0.0235026 | 188.021

# IfcColumn: kolom_gen_ø323.9x8 (11)
In: 00 begane grond
Type - PredefinedType: COLUMN; Material: h2_staal_S355
Classification: 28.11.21 (Uniformat)
BaseQuantities - Length: 3529 mm; CrossSectionArea: 0.0823861 m2; OuterSurfaceArea: 7.00456 m2; GrossVolume: 0.29074 m3; NetVolume: 0.0280169 m3
Tielemans_Column_PSET - Soortelijk_gewicht: 8000 kg/m3; Type: kolom_gen_ø323.9x8; Description: kol. ø323.9x8; Structural Material: h2_staal_S355; Assembly Code: 28.11.21; Phase Created: 2. nieuwbouw; Staalkwaliteit: S355; Volume: 0.0280169 m3; Massa: 224.135 kg
Name (NLRS_28_SC_TLB_kolom buis_gen_AT:kolom_gen_ø323.9x8:...)
837630
837848
838272
838276
845609
845669
846864
846944
847042
856973
857019

# IfcColumn: opstorting vierkant_gen_lxb 400x400 (62)
In: 00 begane grond
Type - PredefinedType: COLUMN; Material: f2_beton ihwg_gen
Classification: 16.10 funderingsconstructies; voeten en balken, algemeen (verzamelniveau) (Uniformat)
BaseQuantities - Length: 400 mm
Tielemans_Column_PSET - LoadBearing: yes; Soortelijk_gewicht: 2500 kg/m3; Type: opstorting vierkant_gen_lxb 400x400; Description: opstort; Assembly Code: 16.10; Assembly Description: funderingsconstructies; voeten en balken, algemeen (verzamelniveau); Phase Created: 2. nieuwbouw; Sterkteklasse: gen
Name (NLRS_16_SC_TLB_opstorting beton_gen_AT:opstorting vierkant_gen_lxb 400x400:...) | CrossSectionArea (m2) | OuterSurfaceArea (m2) | GrossVolume (m3) | NetVolume (m3) = Volume (m3) | Massa (kg)
990697 | 0.142487 | 0.695826 | 0.056995 | 0.056995 | 142.487
991016 | 0.16 | 0.64 | 0.064 | 0.064 | 160
991025 | 0.16 | 0.64 | 0.064 | 0.064 | 160
991036 | 0.16 | 0.64 | 0.064 | 0.064 | 160
991085 | 0.019 | 0.358 | 0.0076 | 0.024 | 60
991100 | 0.16 | 0.64 | 0.064 | 0.064 | 160
991115 | 0.16 | 0.64 | 0.064 | 0.064 | 160
991133 | 0.16 | 0.64 | 0.064 | 0.064 | 160
991186 | 0.16 | 0.64 | 0.064 | 0.064 | 160
991195 | 0.16 | 0.64 | 0.064 | 0.064 | 160
991206 | 0.16 | 0.64 | 0.064 | 0.064 | 160
991224 | 0.16 | 0.64 | 0.064 | 0.064 | 160
991345 | 0.16 | 0.64 | 0.064 | 0.064 | 160
991358 | 0.16 | 0.64 | 0.064 | 0.064 | 160
991441 | 0.16 | 0.64 | 0.064 | 0.064 | 160
991454 | 0.16 | 0.64 | 0.064 | 0.064 | 160
991513 | 0.16 | 0.64 | 0.064 | 0.064 | 160
991534 | 0.16 | 0.64 | 0.064 | 0.064 | 160
991547 | 0.16 | 0.64 | 0.064 | 0.064 | 160
991644 | 0.16 | 0.64 | 0.064 | 0.064 | 160
991662 | 0.16 | 0.64 | 0.064 | 0.064 | 160
991671 | 0.16 | 0.64 | 0.064 | 0.064 | 160
991682 | 0.16 | 0.64 | 0.064 | 0.064 | 160
991689 | 0.16 | 0.64 | 0.064 | 0.064 | 160
991698 | 0.16 | 0.64 | 0.064 | 0.064 | 160
991709 | 0.16 | 0.64 | 0.064 | 0.064 | 160
991718 | 0.16 | 0.64 | 0.064 | 0.064 | 160
991790 | 0.16 | 0.64 | 0.064 | 0.064 | 160
991850 | 0.16 | 0.64 | 0.064 | 0.064 | 160
992003 | 0.0375085 | 0.384466 | 0.0150034 | 0.0232434 | 58.1085
992119 | 0.0398096 | 0.4064 | 0.0159238 | 0.023634 | 59.085
992192 | 0.16 | 0.64 | 0.064 | 0.064 | 160
992272 | 0.0377465 | 0.530006 | 0.0150986 | 0.0198949 | 49.7372
992283 | 0.03 | 0.38 | 0.012 | 0.024 | 60
992294 | 0.03 | 0.38 | 0.012 | 0.024 | 60
992305 | 0.03 | 0.38 | 0.012 | 0.024 | 60
992314 | 0.16 | 0.64 | 0.064 | 0.064 | 160
992325 | 0.16 | 0.64 | 0.064 | 0.064 | 160
992355 | 0.03 | 0.38 | 0.012 | 0.024 | 60
992368 | 0.03 | 0.38 | 0.012 | 0.024 | 60
992381 | 0.16 | 0.64 | 0.064 | 0.064 | 160
992390 | 0.16 | 0.64 | 0.064 | 0.064 | 160
992399 | 0.16 | 0.64 | 0.064 | 0.064 | 160
992408 | 0.16 | 0.64 | 0.064 | 0.064 | 160
992419 | 0.16 | 0.64 | 0.064 | 0.064 | 160
992428 | 0.16 | 0.64 | 0.064 | 0.064 | 160
992437 | 0.16 | 0.64 | 0.064 | 0.064 | 160
992452 | 0.136771 | 0.593543 | 0.0547086 | 0.0547086 | 136.771
992465 | 0.16 | 0.64 | 0.064 | 0.064 | 160
992474 | 0.16 | 0.64 | 0.064 | 0.064 | 160
992483 | 0.16 | 0.64 | 0.064 | 0.064 | 160
992494 | 0.16 | 0.64 | 0.064 | 0.064 | 160
992507 | 0.16 | 0.64 | 0.064 | 0.064 | 160
992518 | 0.16 | 0.64 | 0.064 | 0.064 | 160
992529 | 0.16 | 0.64 | 0.064 | 0.064 | 160
992540 | 0.16 | 0.64 | 0.064 | 0.064 | 160
992549 | 0.16 | 0.64 | 0.064 | 0.064 | 160
992560 | 0.16 | 0.64 | 0.064 | 0.064 | 160
992569 | 0.16 | 0.64 | 0.064 | 0.064 | 160
992582 | 0.16 | 0.64 | 0.064 | 0.064 | 160
992688 | 0.0110453 | 0.219069 | 0.00441813 | 0.0188019 | 47.0047
1001945 | 0.16 | 0.64 | 0.064 | 0.064 | 160

# IfcColumn: opstorting vierkant_gen_lxb 500x1000 (2)
In: 00 begane grond
Type - PredefinedType: COLUMN; Material: f2_beton ihwg_gen
Classification: 16.10 funderingsconstructies; voeten en balken, algemeen (verzamelniveau) (Uniformat)
BaseQuantities - Length: 1104 mm; CrossSectionArea: 0.275 m2; OuterSurfaceArea: 2.8152 m2; GrossVolume: 0.3036 m3; NetVolume: 0.3036 m3
Tielemans_Column_PSET - LoadBearing: yes; Soortelijk_gewicht: 2500 kg/m3; Type: opstorting vierkant_gen_lxb 500x1000; Description: opstort; Assembly Code: 16.10; Assembly Description: funderingsconstructies; voeten en balken, algemeen (verzamelniveau); Phase Created: 2. nieuwbouw; Sterkteklasse: gen; Volume: 0.3036 m3; Massa: 759 kg
Name (NLRS_16_SC_TLB_opstorting beton_gen_AT:opstorting vierkant_gen_lxb 500x1000:...)
997060
997326

# IfcColumn: opstorting vierkant_gen_lxb 500x500 (17)
In: 00 begane grond
Type - PredefinedType: COLUMN; Material: f2_beton ihwg_gen
Classification: 16.10 funderingsconstructies; voeten en balken, algemeen (verzamelniveau) (Uniformat)
Tielemans_Column_PSET - LoadBearing: yes; Soortelijk_gewicht: 2500 kg/m3; Type: opstorting vierkant_gen_lxb 500x500; Description: opstort; Assembly Code: 16.10; Assembly Description: funderingsconstructies; voeten en balken, algemeen (verzamelniveau); Phase Created: 2. nieuwbouw; Sterkteklasse: gen
Name (NLRS_16_SC_TLB_opstorting beton_gen_AT:opstorting vierkant_gen_lxb 500x500:...) | Length (mm) | CrossSectionArea (m2) | OuterSurfaceArea (m2) | GrossVolume (m3) | NetVolume (m3) = Volume (m3) | Massa (kg)
991124 | 400 | 0.25 | 0.8 | 0.1 | 0.1 | 250
991215 | 400 | 0.25 | 0.8 | 0.1 | 0.1 | 250
991428 | 400 | 0.25 | 0.8 | 0.1 | 0.1 | 250
991653 | 400 | 0.25 | 0.8 | 0.1 | 0.1 | 250
992209 | 400 | 0.25 | 0.8 | 0.1 | 0.1 | 250
992220 | 400 | 0.25 | 0.8 | 0.1 | 0.1 | 250
992242 | 400 | 0.25 | 0.8 | 0.1 | 0.1 | 250
992261 | 400 | 0.25 | 0.8 | 0.1 | 0.1 | 250
992336 | 400 | 0.25 | 0.8 | 0.1 | 0.1 | 250
997317 | 1104 | 0.059125 | 1.08192 | 0.065274 | 0.065274 | 163.185
997337 | 1104 | 0.075625 | 1.2144 | 0.08349 | 0.08349 | 208.725
997348 | 1104 | 0.1375 | 1.7112 | 0.1518 | 0.1518 | 379.5
997357 | 1104 | 0.1375 | 1.7112 | 0.1518 | 0.1518 | 379.5
997366 |  | 0.7524 |  |  | 0.0592 | 148
997450 |  | 0.8199 |  |  | 0.0722 | 180.5
1001347 | 400 | 0.25 | 0.8 | 0.1 | 0.1 | 250
1001418 | 400 | 0.00891424 | 0.222061 | 0.0035657 | 0.052047 | 130.118

# IfcFooting: NLRS_13_SFO_fundatievloer_300_gen_AT, Foundation Slab:NLRS_13_SFO_fundatievloer_300_gen_AT:996938
In: 00 begane grond
Type - Material: f2_beton ihwg_gen 300 mm
Classification: 13.22 vloeren op grondslag; constructief, vloeren als gebouwonderdeel (Uniformat)
Tielemans_ Foundation_PSET - LoadBearing: yes; Soortelijk_gewicht: 2500 kg/m3; Type: NLRS_13_SFO_fundatievloer_300_gen_AT; Description: betonvloer d=300; Structural Material: f2_beton ihwg_gen; Assembly Code: 13.22; Assembly Description: vloeren op grondslag; constructief, vloeren als gebouwonderdeel; Phase Created: 2. nieuwbouw; Sterkteklasse: gen; Volume: 56.6766 m3; Massa: 141692 kg; Onderzijde tov Peil: -1454 mm

# IfcFooting: NLRS_13_SFO_fundatievloer_350_gen_AT (2)
In: 00 begane grond
Type - Material: f2_beton ihwg_gen 350 mm
Classification: 13.22 vloeren op grondslag; constructief, vloeren als gebouwonderdeel (Uniformat)
Tielemans_ Foundation_PSET - LoadBearing: yes; Soortelijk_gewicht: 2500 kg/m3; Type: NLRS_13_SFO_fundatievloer_350_gen_AT; Description: betonvloer d=350; Structural Material: f2_beton ihwg_gen; Assembly Code: 13.22; Assembly Description: vloeren op grondslag; constructief, vloeren als gebouwonderdeel; Phase Created: 2. nieuwbouw; Sterkteklasse: gen; Onderzijde tov Peil: -1550 mm
Name (Foundation Slab:NLRS_13_SFO_fundatievloer_350_gen_AT:...) | Volume (m3) | Massa (kg)
993678 | 6.09434 | 15235.8
995688 | 3.77783 | 9444.57

# IfcFooting: fundatiepoer_gen_lxbxh 2250x2100x1100 (29)
In: 00 begane grond
Type - Material: f2_beton ihwg_gen
Classification: 16.13 funderingsconstructies; voeten en balken, fundatie poeren (Uniformat)
Tielemans_ Foundation_PSET - LoadBearing: yes; Soortelijk_gewicht: 2500 kg/m3; Type: fundatiepoer_gen_lxbxh 2250x2100x1100; Description: poer 2250x2100x1100; Structural Material: f2_beton ihwg_gen; Assembly Code: 16.13; Assembly Description: funderingsconstructies; voeten en balken, fundatie poeren; Phase Created: 2. nieuwbouw; Sterkteklasse: gen; Type Mark: poer 2250x2100x1100
Name (NLRS_16_SFO_fundatiepoer_gen_AT:fundatiepoer_gen_lxbxh 2250x2100x1100:...) | Volume (m3) | Massa (kg) | Onderzijde tov Peil (mm)
1026071 | 5.1975 | 12993.8 | -1650
1026773 | 3.78 | 9450 | -2254
1027425 | 3.78 | 9450 | -2254
1027448 | 4.27654 | 10691.3 | -2254
1028352 | 5.1975 | 12993.8 | -1650
1028363 | 5.1975 | 12993.8 | -1650
1028374 | 5.1975 | 12993.8 | -1650
1028385 | 5.1975 | 12993.8 | -1650
1028698 | 5.1975 | 12993.8 | -1650
1028710 | 5.1975 | 12993.8 | -1650
1028883 | 5.1975 | 12993.8 | -1650
1028894 | 5.1975 | 12993.8 | -1650
1028905 | 5.1975 | 12993.8 | -1650
1028916 | 5.1975 | 12993.8 | -1650
1029061 | 5.1975 | 12993.8 | -1650
1029366 | 5.1975 | 12993.8 | -1650
1029377 | 5.1975 | 12993.8 | -1650
1029388 | 5.1975 | 12993.8 | -1650
1029399 | 5.1975 | 12993.8 | -1650
1029410 | 5.1975 | 12993.8 | -1650
1029421 | 5.1975 | 12993.8 | -1650
1029434 | 5.1975 | 12993.8 | -1650
1029591 | 5.1975 | 12993.7 | -1650
1029606 | 5.1975 | 12993.7 | -1650
1029617 | 5.1975 | 12993.7 | -1650
1029628 | 5.1975 | 12993.7 | -1650
1029956 | 3.90544 | 9763.61 | -2254
1030162 | 3.90544 | 9763.61 | -2254
1030381 | 4.26435 | 10660.9 | -2254

# IfcFooting: fundatiepoer_gen_lxbxh 2250x600x900 (17)
In: 00 begane grond
Type - Material: f2_beton ihwg_gen
Classification: 16.13 funderingsconstructies; voeten en balken, fundatie poeren (Uniformat)
Tielemans_ Foundation_PSET - LoadBearing: yes; Soortelijk_gewicht: 2500 kg/m3; Type: fundatiepoer_gen_lxbxh 2250x600x900; Description: poer 2250x600x900; Structural Material: f2_beton ihwg_gen; Assembly Code: 16.13; Assembly Description: funderingsconstructies; voeten en balken, fundatie poeren; Phase Created: 2. nieuwbouw; Sterkteklasse: gen; Volume: 1.215 m3; Massa: 3037.5 kg; Onderzijde tov Peil: -1350 mm; Type Mark: poer 2250x600x900
Name (NLRS_16_SFO_fundatiepoer_gen_AT:fundatiepoer_gen_lxbxh 2250x600x900:...)
1022480
1022596
1022604
1022616
1022691
1022758
1022823
1022829
1022835
1022843
1022950
1023794
1023802
1023810
1023899
1023973
1023981

# IfcFooting: fundatiepoer_gen_lxbxh 2250x700x900 (4)
In: 00 begane grond
Type - Material: f2_beton ihwg_gen
Classification: 16.13 funderingsconstructies; voeten en balken, fundatie poeren (Uniformat)
Tielemans_ Foundation_PSET - LoadBearing: yes; Soortelijk_gewicht: 2500 kg/m3; Type: fundatiepoer_gen_lxbxh 2250x700x900; Description: poer 2250x700x900; Structural Material: f2_beton ihwg_gen; Assembly Code: 16.13; Assembly Description: funderingsconstructies; voeten en balken, fundatie poeren; Phase Created: 2. nieuwbouw; Sterkteklasse: gen; Volume: 1.4175 m3; Massa: 3543.75 kg; Onderzijde tov Peil: -1350 mm; Type Mark: poer 2250x700x900
Name (NLRS_16_SFO_fundatiepoer_gen_AT:fundatiepoer_gen_lxbxh 2250x700x900:...)
1037937
1038055
1038065
1038077

# IfcOpeningElement: Opening (29)
Name | In | Width (mm) | Height (mm)
Basic Wall:NLRS_22_WA_kalkzandsteen 214_CS20_gen_AT:835387:1 | 00 begane grond | 214 | Classification: 22.21 binnenwanden; constructief, massieve wanden (Uniformat); Tielemans_Wall_PSET - Structural Usage: Bearing; Soortelijk_gewicht: 1850 kg/m3; Type: NLRS_22_WA_kalkzandsteen 214_CS20_gen_AT; Structural Material: f1_kalkzandsteen_CS20; Genormaliseerde steendruksterkte: CS20; Assembly Code: 22.21; Assembly Description: binnenwanden; constructief, massieve wanden; Phase Created: 2. nieuwbouw; Volume: 2.66791 m3; Massa: 4935.64 kg; BaseQuantities - Area: 12.4669 m2; Volume: 8.75299 m3
Floor:NLRS_23_FL_kanaalplaatvloer 260_gen_AT:871925 | 01 eerste verdieping | 1425 | 2700
Floor:NLRS_23_FL_kanaalplaatvloer 260_gen_AT:871925 | 01 eerste verdieping | 3010 | 2260
Floor:NLRS_23_FL_gewapende druklaag beton_60_gen_AT:889397 | 01 eerste verdieping | 1425 | 2700
Floor:NLRS_23_FL_gewapende druklaag beton_60_gen_AT:889397 | 01 eerste verdieping | 1545 | 545
Floor:NLRS_23_FL_gewapende druklaag beton_60_gen_AT:889397 | 01 eerste verdieping | 7740 | 8540
Floor:NLRS_23_FL_gewapende druklaag beton_60_gen_AT:889397 | 01 eerste verdieping | 2356 | 3846.5
Floor:NLRS_23_FL_gewapende druklaag beton_60_gen_AT:889397 | 01 eerste verdieping | 3010 | 2260
2 x Floor:NLRS_23_FL_gewapende druklaag beton_60_gen_AT:889397 | 02 tweede verdieping | 7740 | 2450
Floor:NLRS_23_FL_gewapende druklaag beton_60_gen_AT:889397 | 02 tweede verdieping | BaseQuantities - Area: 9.01068 m2
Floor:NLRS_23_FL_gewapende druklaag beton_60_gen_AT:889397 | 02 tweede verdieping | 7745 | 2450
2 x  | 02 tweede verdieping | 7750 | 2450 | Classification: 23.21 vloeren; constructief, vrijdragende vloeren (Uniformat); BaseQuantities - Area: 0 m2; Volume: 24.0326 m3; Depth: 260 mm; Tielemans_Floor_PSET - Soortelijk_gewicht: 2500 kg/m3; Structural: yes; Type: NLRS_23_FL_kanaalplaatvloer 260_gen_AT; Description: kpv260+gewapdrkl 60; Structural Material: f2_beton_prefab_gen; Sterkteklasse: gen; Assembly Code: 23.21; Assembly Description: vloeren; constructief, vrijdragende vloeren; Phase Created: 2. nieuwbouw; Volume: 7.32514 m3; Massa: 18312.8 kg
2 x Floor:NLRS_23_FL_kanaalplaatvloer 260_gen_AT:871925 | 02 tweede verdieping | 2400 | 3600
2 x Floor:NLRS_23_FL_gewapende druklaag beton_60_gen_AT:889397 | 02 tweede verdieping | 2400 | 3600
Floor:NLRS_23_FL_gewapende druklaag beton_60_gen_AT:889397 | 02 tweede verdieping | 3010 | 2260
Floor:NLRS_23_FL_gewapend beton_400_opstort gen_AT:989437 | 00 begane grond | 2260 | 3010
Floor:NLRS_23_FL_gewapend beton_400_opstort gen_AT:989437 | 00 begane grond | 1600 | 2422
Floor:NLRS_23_FL_gewapend beton_400_opstort gen_AT:989437 | 00 begane grond | BaseQuantities - Area: 153.952 m2
Floor:NLRS_23_FL_geissoleerde kanaalplaatvloer 260_gen_AT:997498 | 00 begane grond | 2760 | 3510
Floor:NLRS_23_FL_kanaalplaatvloer 260_gen_AT:871925 | 02 tweede verdieping | 2260 | 3010
Basic Wall:NLRS_22_WA_kalkzandsteen 214_CS20_gen_AT:845404 | 00 begane grond | 1450 | 2400 | BaseQuantities - Depth: 3048 mm
Basic Wall:NLRS_22_WA_kalkzandsteen 214_CS20_gen_AT:868468 | 00 begane grond | 1050 | 2400 | BaseQuantities - Depth: 3048 mm
Basic Wall:NLRS_22_WA_kalkzandsteen 214_CS20_gen_AT:892007 | 01 eerste verdieping | 1450 | 2400 | BaseQuantities - Depth: 3048 mm
Basic Wall:NLRS_22_WA_kalkzandsteen 214_CS20_gen_AT:892015 | 01 eerste verdieping | 1050 | 2400 | BaseQuantities - Depth: 3048 mm
Basic Wall:NLRS_22_WA_kalkzandsteen 214_CS20_gen_AT:935057 | 02 tweede verdieping | 1450 | 2400 | BaseQuantities - Depth: 3048 mm

# IfcPile: Type 4_a-1 (18)
In: 00 begane grond
Type - Material: f2_beton ihwg_C30/37
Classification: 17.10 paalfunderingen; niet geheid, algemeen (verzamelniveau) (Uniformat)
Tielemans_ Foundation_PSET - LoadBearing: yes; Soortelijk_gewicht: 2500 kg/m3; Type: Type 4_a-1; Description: ̤450; Structural Material: f2_beton ihwg_C30/37; Paaltype: avegaarpaal; wapeningskorf: vlgs. leverancier; Assembly Code: 17.10; Assembly Description: paalfunderingen; niet geheid, algemeen (verzamelniveau); Phase Created: 2. nieuwbouw; Sterkteklasse: C30/37; Volume: 2.83345 m3; Massa: 7083.63 kg; bovenzijde_paal_tov_peil: -2234 mm; bovenzijde_paal_tov_NAP: 18816 mm; Onderzijde tov Peil: -20050 mm; paalpuntniveau_tov_NAP: 1000 mm; Type Mark: a-1
BaseQuantities - Length: 17816 mm; CrossSectionArea: 0.15902 m2; OuterSurfaceArea: 25.1868 m2; GrossSurfaceArea: 25.5048 m2; GrossVolume: 2.83311 m3; NetVolume: 2.83345 m3
Name (NLRS_17_SFO_fundatiepaal_rond_gen_AT:Type 4_a-1:...) | Mark
1026992 | 77
1027276 | 76
1027284 | 107
1027426 | 75
1027427 | 74
1027428 | 106
1027449 | 79
1027450 | 78
1027451 | 108
1029957 | 179
1029958 | 180
1029959 | 169
1030163 | 181
1030164 | 182
1030165 | 170
1030382 | 183
1030383 | 184
1030384 | 171

# IfcPile: Type 4_a-2 (3)
In: 00 begane grond
Type - Material: f2_beton ihwg_C30/37
Classification: 17.10 paalfunderingen; niet geheid, algemeen (verzamelniveau) (Uniformat)
Tielemans_ Foundation_PSET - LoadBearing: yes; Soortelijk_gewicht: 2500 kg/m3; Type: Type 4_a-2; Description: ̤450; Structural Material: f2_beton ihwg_C30/37; Paaltype: avegaarpaal; wapeningskorf: vlgs. leverancier; Assembly Code: 17.10; Assembly Description: paalfunderingen; niet geheid, algemeen (verzamelniveau); Phase Created: 2. nieuwbouw; Sterkteklasse: C30/37; Volume: 2.91297 m3; Massa: 7282.43 kg; bovenzijde_paal_tov_peil: -1734 mm; bovenzijde_paal_tov_NAP: 19316 mm; Onderzijde tov Peil: -20050 mm; paalpuntniveau_tov_NAP: 1000 mm; Type Mark: a-2
BaseQuantities - Length: 18316 mm; CrossSectionArea: 0.15902 m2; OuterSurfaceArea: 25.8936 m2; GrossSurfaceArea: 26.2117 m2; GrossVolume: 2.91262 m3; NetVolume: 2.91297 m3
Name (NLRS_17_SFO_fundatiepaal_rond_gen_AT:Type 4_a-2:...) | Mark
1027954 | 134
1031238 | 135
1031289 | 133

# IfcPile: Type 4_a-3 (69)
In: 00 begane grond
Type - Material: f2_beton ihwg_C30/37
Classification: 17.10 paalfunderingen; niet geheid, algemeen (verzamelniveau) (Uniformat)
Tielemans_ Foundation_PSET - LoadBearing: yes; Soortelijk_gewicht: 2500 kg/m3; Type: Type 4_a-3; Description: ̤450; Structural Material: f2_beton ihwg_C30/37; Paaltype: avegaarpaal; wapeningskorf: vlgs. leverancier; Assembly Code: 17.10; Assembly Description: paalfunderingen; niet geheid, algemeen (verzamelniveau); Phase Created: 2. nieuwbouw; Sterkteklasse: C30/37; Volume: 2.92951 m3; Massa: 7323.78 kg; bovenzijde_paal_tov_peil: -1630 mm; bovenzijde_paal_tov_NAP: 19420 mm; Onderzijde tov Peil: -20050 mm; paalpuntniveau_tov_NAP: 1000 mm; Type Mark: a-3
BaseQuantities - Length: 18420 mm; CrossSectionArea: 0.15902 m2; OuterSurfaceArea: 26.0407 m2; GrossSurfaceArea: 26.3587 m2; GrossVolume: 2.92916 m3; NetVolume: 2.92951 m3
Name (NLRS_17_SFO_fundatiepaal_rond_gen_AT:Type 4_a-3:...) | Mark
1028063 | 89
1028161 | 88
1028171 | 113
1028353 | 87
1028354 | 86
1028355 | 112
1028364 | 85
1028365 | 84
1028366 | 111
1028375 | 83
1028376 | 82
1028377 | 110
1028386 | 81
1028387 | 80
1028388 | 109
1028699 | 91
1028700 | 90
1028711 | 93
1028712 | 92
1028756 | 114
1028762 | 115
1028884 | 95
1028885 | 94
1028886 | 116
1028895 | 97
1028896 | 96
1028897 | 117
1028906 | 99
1028907 | 98
1028908 | 118
1028917 | 101
1028918 | 100
1028919 | 119
1029062 | 166
1029063 | 167
1029064 | 146
1029367 | 164
1029368 | 165
1029369 | 145
1029378 | 162
1029379 | 163
1029380 | 144
1029389 | 160
1029390 | 161
1029391 | 143
1029400 | 158
1029401 | 159
1029402 | 142
1029411 | 156
1029412 | 157
1029413 | 141
1029422 | 154
1029423 | 155
1029424 | 140
1029435 | 152
1029436 | 153
1029437 | 139
1029592 | 191
1029593 | 192
1029594 | 175
1029607 | 189
1029608 | 190
1029609 | 174
1029618 | 187
1029619 | 188
1029620 | 173
1029629 | 185
1029630 | 186
1029631 | 172

# IfcPile: Type 4_a-4 (8)
In: 00 begane grond
Type - Material: f2_beton ihwg_C30/37
Classification: 17.10 paalfunderingen; niet geheid, algemeen (verzamelniveau) (Uniformat)
Tielemans_ Foundation_PSET - LoadBearing: yes; Soortelijk_gewicht: 2500 kg/m3; Type: Type 4_a-4; Description: ̤450; Structural Material: f2_beton ihwg_C30/37; Paaltype: avegaarpaal; wapeningskorf: vlgs. leverancier; Assembly Code: 17.10; Assembly Description: paalfunderingen; niet geheid, algemeen (verzamelniveau); Phase Created: 2. nieuwbouw; Sterkteklasse: C30/37; Volume: 2.94542 m3; Massa: 7363.54 kg; bovenzijde_paal_tov_peil: -1530 mm; bovenzijde_paal_tov_NAP: 19520 mm; Onderzijde tov Peil: -20050 mm; paalpuntniveau_tov_NAP: 1000 mm; Type Mark: a-4
BaseQuantities - Length: 18520 mm; CrossSectionArea: 0.15902 m2; OuterSurfaceArea: 26.182 m2; GrossSurfaceArea: 26.5001 m2; GrossVolume: 2.94506 m3; NetVolume: 2.94542 m3
Name (NLRS_17_SFO_fundatiepaal_rond_gen_AT:Type 4_a-4:...) | Mark
1031359 | 102
1031473 | 103
1031481 | 126
1031538 | 125
1032069 | 62
1032147 | 67
1032191 | 104
1032706 | 70

# IfcPile: Type 4_a-5 (6)
In: 00 begane grond
Type - Material: f2_beton ihwg_C30/37
Classification: 17.10 paalfunderingen; niet geheid, algemeen (verzamelniveau) (Uniformat)
Tielemans_ Foundation_PSET - LoadBearing: yes; Soortelijk_gewicht: 2500 kg/m3; Type: Type 4_a-5; Description: ̤450; Structural Material: f2_beton ihwg_C30/37; Paaltype: avegaarpaal; wapeningskorf: vlgs. leverancier; Assembly Code: 17.10; Assembly Description: paalfunderingen; niet geheid, algemeen (verzamelniveau); Phase Created: 2. nieuwbouw; Sterkteklasse: C30/37; Volume: 2.96068 m3; Massa: 7401.71 kg; bovenzijde_paal_tov_peil: -1434 mm; bovenzijde_paal_tov_NAP: 19616 mm; Onderzijde tov Peil: -20050 mm; paalpuntniveau_tov_NAP: 1000 mm; Type Mark: a-5
BaseQuantities - Length: 18616 mm; CrossSectionArea: 0.15902 m2; OuterSurfaceArea: 26.3177 m2; GrossSurfaceArea: 26.6358 m2; GrossVolume: 2.96032 m3; NetVolume: 2.96068 m3
Name (NLRS_17_SFO_fundatiepaal_rond_gen_AT:Type 4_a-5:...) | Mark
1031675 | 127
1031818 | 105
1031828 | 68
1031868 | 69
1032025 | 178
1033966 | 148

# IfcPile: Type 4_a-6 (42)
In: 00 begane grond
Type - Material: f2_beton ihwg_C30/37
Classification: 17.10 paalfunderingen; niet geheid, algemeen (verzamelniveau) (Uniformat)
Tielemans_ Foundation_PSET - LoadBearing: yes; Soortelijk_gewicht: 2500 kg/m3; Type: Type 4_a-6; Description: ̤450; Structural Material: f2_beton ihwg_C30/37; Paaltype: avegaarpaal; wapeningskorf: vlgs. leverancier; Assembly Code: 17.10; Assembly Description: paalfunderingen; niet geheid, algemeen (verzamelniveau); Phase Created: 2. nieuwbouw; Sterkteklasse: C30/37; Volume: 2.97722 m3; Massa: 7443.06 kg; bovenzijde_paal_tov_peil: -1330 mm; bovenzijde_paal_tov_NAP: 19720 mm; Onderzijde tov Peil: -20050 mm; paalpuntniveau_tov_NAP: 1000 mm; Type Mark: a-6
BaseQuantities - Length: 18720 mm; CrossSectionArea: 0.15902 m2; OuterSurfaceArea: 26.4648 m2; GrossSurfaceArea: 26.7828 m2; GrossVolume: 2.97686 m3; NetVolume: 2.97722 m3
Name (NLRS_17_SFO_fundatiepaal_rond_gen_AT:Type 4_a-6:...) | Mark
1033049 | 46
1033140 | 50
1033216 | 55
1033217 | 56
1033225 | 60
1033226 | 64
1033234 | 72
1033235 | 73
1033245 | 51
1033246 | 53
1033446 | 21
1033447 | 45
1033455 | 17
1033456 | 20
1033464 | 14
1033465 | 15
1033473 | 9
1033474 | 11
1033484 | 6
1033485 | 8
1033728 | 196
1033818 | 197
1033869 | 201
1033870 | 207
1033880 | 230
1033881 | 233
1033891 | 200
1033892 | 205
1033900 | 193
1033901 | 195
1033909 | 168
1033910 | 177
1033922 | 132
1033923 | 137
1037938 | 120
1037939 | 123
1038056 | 66
1038057 | 71
1038066 | 129
1038067 | 131
1038078 | 147
1038079 | 151

# IfcPile: Type 4_a-7 (93)
In: 00 begane grond
Type - Material: f2_beton ihwg_C30/37
Classification: 17.10 paalfunderingen; niet geheid, algemeen (verzamelniveau) (Uniformat)
Tielemans_ Foundation_PSET - LoadBearing: yes; Soortelijk_gewicht: 2500 kg/m3; Type: Type 4_a-7; Description: ̤450; Structural Material: f2_beton ihwg_C30/37; Paaltype: avegaarpaal; wapeningskorf: vlgs. leverancier; Assembly Code: 17.10; Assembly Description: paalfunderingen; niet geheid, algemeen (verzamelniveau); Phase Created: 2. nieuwbouw; Sterkteklasse: C30/37; Volume: 3.02494 m3; Massa: 7562.34 kg; bovenzijde_paal_tov_peil: -1030 mm; bovenzijde_paal_tov_NAP: 20020 mm; Onderzijde tov Peil: -20050 mm; paalpuntniveau_tov_NAP: 1000 mm; Type Mark: a-7
BaseQuantities - Length: 19020 mm; CrossSectionArea: 0.15902 m2; OuterSurfaceArea: 26.8889 m2; GrossSurfaceArea: 27.2069 m2; GrossVolume: 3.02457 m3; NetVolume: 3.02494 m3
Name (NLRS_17_SFO_fundatiepaal_rond_gen_AT:Type 4_a-7:...) | Mark
1034111 | 149
1034154 | 136
1034341 | 128
1034928 | 65
1034986 | 121
1035054 | 122
1035114 | 63
1035303 | 47
1035357 | 43
1035504 | 42
1035589 | 41
1035597 | 40
1035607 | 39
1035666 | 38
1035680 | 37
1035688 | 36
1035696 | 35
1035704 | 34
1035710 | 33
1035783 | 150
1035791 | 206
1035837 | 229
1035920 | 228
1036014 | 227
1036022 | 226
1036030 | 225
1036038 | 224
1036046 | 223
1036054 | 222
1036062 | 221
1036070 | 220
1036078 | 219
1036088 | 204
1036166 | 203
1036231 | 202
1036297 | 49
1036372 | 48
1036433 | 32
1036443 | 31
1036451 | 30
1036459 | 29
1036467 | 28
1036473 | 27
1036481 | 26
1036489 | 25
1036497 | 24
1036505 | 23
1036517 | 22
1036527 | 44
1036913 | 18
1037108 | 16
1037116 | 13
1037258 | 10
1037357 | 7
1037365 | 4
1037373 | 3
1037421 | 1
1037488 | 2
1037619 | 5
1037629 | 12
1037637 | 19
1037645 | 52
1037653 | 58
1037689 | 61
1037787 | 176
1038103 | 199
1038148 | 138
1038184 | 124
1038192 | 57
1038722 | 232
1038782 | 236
1038860 | 239
1038896 | 238
1038975 | 237
1038983 | 235
1038991 | 234
1039003 | 231
1039229 | 218
1039353 | 217
1039361 | 216
1039369 | 215
1039385 | 214
1039397 | 213
1039538 | 212
1039552 | 210
1039560 | 209
1039570 | 211
1039584 | 208
1039652 | 198
1040695 | 194
1040784 | 59
1040891 | 54
1041001 | 130

# IfcSlab: NLRS_23_FL_geissoleerde kanaalplaatvloer 260_gen_AT (9)
In: 00 begane grond
Type - PredefinedType: FLOOR; Material: f2_beton_prefab_gen 260 mm, n7_isolatie_gen 140 mm
Classification: 23.21 vloeren; constructief, vrijdragende vloeren (Uniformat)
Tielemans_Floor_PSET - LoadBearing: yes; Soortelijk_gewicht: 2500 kg/m3; Structural: yes; Type: NLRS_23_FL_geissoleerde kanaalplaatvloer 260_gen_AT; Description: geissol. kpv260; Structural Material: f2_beton_prefab_gen; Sterkteklasse: gen; Assembly Code: 23.21; Assembly Description: vloeren; constructief, vrijdragende vloeren; Phase Created: 2. nieuwbouw
Name (Floor:NLRS_23_FL_geissoleerde kanaalplaatvloer 260_gen_AT:...) | Volume (m3) = NetVolume (m3) | Massa (kg) | Perimeter (mm) | GrossArea (m2) | NetArea (m2) | GrossVolume (m3)
997495 | 284.189 | 710472 | 528.581 | 710.472 | 710.472 | 284.189
999141 | 190.072 | 475181 | 448.399 | 475.501 | 475.181 | 190.2
999400 | 257.456 | 643640 | 515.958 | 643.64 | 643.64 | 257.456
999993 | 51.4051 | 128513 | 177.304 | 128.512 | 128.512 | 51.405
1000438 | 44.618 | 111545 | 198.301 | 111.545 | 111.545 | 44.618
1001455 | 67.3614 | 168404 | 205.535 | 168.404 | 168.404 | 67.3614
1001876 | 109.248 | 273121 | 234.744 | 273.121 | 273.121 | 109.248
1001975 | 110.266 | 275665 | 233.914 | 275.665 | 275.665 | 110.266
1023219 | 68.0345 | 170086 | 304.891 | 180.094 | 170.086 | 72.0376

# IfcSlab: NLRS_23_FL_gewapend beton_400_opstort gen_AT (5)
In: 00 begane grond
Type - PredefinedType: FLOOR; Material: f2_beton ihwg_gen 400 mm
Classification: 23.20 vloeren; constructief, algemeen (verzamelniveau) (Uniformat)
Tielemans_Floor_PSET - Soortelijk_gewicht: 2500 kg/m3; Structural: yes; Type: NLRS_23_FL_gewapend beton_400_opstort gen_AT; Description: opstort; Structural Material: f2_beton ihwg_gen; Sterkteklasse: gen; Assembly Code: 23.20; Assembly Description: vloeren; constructief, algemeen (verzamelniveau); Phase Created: 2. nieuwbouw
Name (Floor:NLRS_23_FL_gewapend beton_400_opstort gen_AT:...) | Volume (m3) = NetVolume (m3) | Massa (kg) | Perimeter (mm) | GrossArea (m2) | NetArea (m2) | GrossVolume (m3)
989434 | 24.8467 | 62116.7 | 1633.21 | 24.0581 | 62.0671 | 9.62325
989434:2 | 24.8467 | 62116.7 | 1633.21 | 37.9415 | 62.0671 | 15.1766
992755 | 1.154 | 2885 | 75.7218 | 9.6876 | 2.885 | 3.87504 | BaseQuantities - Width: 3510 mm
995524 | 0.9044 | 2261 | 59.3438 | 6.1362 | 2.261 | 2.45448 | BaseQuantities - Width: 2100 mm
995880 | 5.22 | 13050 | 342.52 | 167.002 | 13.05 | 66.8008

# IfcSlab: NLRS_23_FL_gewapende druklaag beton_60_gen_AT (7)
Type - PredefinedType: FLOOR; Material: f2_beton ihwg_gen 60 mm
Classification: 23.20 vloeren; constructief, algemeen (verzamelniveau) (Uniformat)
Tielemans_Floor_PSET - Soortelijk_gewicht: 2500 kg/m3; Structural: yes; Type: NLRS_23_FL_gewapende druklaag beton_60_gen_AT; Description: gewap.drukl. d=60; Structural Material: f2_beton ihwg_gen; Sterkteklasse: gen; Assembly Code: 23.20; Assembly Description: vloeren; constructief, algemeen (verzamelniveau); Phase Created: 2. nieuwbouw
Name (Floor:NLRS_23_FL_gewapende druklaag beton_60_gen_AT:...) | In | Volume (m3) = NetVolume (m3) | Massa (kg) | Perimeter (mm) | GrossArea (m2) | NetArea (m2) | GrossVolume (m3)
889430 | 01 eerste verdieping | 118.628 | 296570 | 809.114 | 2056.86 | 1977.01 | 123.412
890445 | 01 eerste verdieping | 21.3652 | 53413.1 | 376.314 | 362.873 | 356.08 | 21.7724
891592 | 01 eerste verdieping | 33.6667 | 84166.8 | 309.662 | 561.086 | 561.096 | 33.6651
891623 | 01 eerste verdieping | 10.0963 | 25240.8 | 208.631 | 168.272 | 168.273 | 10.0963
920107 | 02 tweede verdieping | 119.981 | 299953 | 886.418 | 2065.59 | 1999.57 | 123.935
924100 | 02 tweede verdieping | 9.72927 | 24323.2 | 208.499 | 179.435 | 162.156 | 10.7661
934938 | 02 tweede verdieping | 25.4557 | 63639.2 | 340.881 | 431.047 | 424.254 | 25.8628

# IfcSlab: NLRS_23_FL_kanaalplaatvloer 260_gen_AT (23)
Type - PredefinedType: FLOOR; Material: f2_beton_prefab_gen 260 mm
Classification: 23.21 vloeren; constructief, vrijdragende vloeren (Uniformat)
Tielemans_Floor_PSET - Soortelijk_gewicht: 2500 kg/m3; Structural: yes; Type: NLRS_23_FL_kanaalplaatvloer 260_gen_AT; Description: kpv260+gewapdrkl 60; Structural Material: f2_beton_prefab_gen; Sterkteklasse: gen; Assembly Code: 23.21; Assembly Description: vloeren; constructief, vrijdragende vloeren; Phase Created: 2. nieuwbouw
Name (Floor:NLRS_23_FL_kanaalplaatvloer 260_gen_AT:...) | In | Volume (m3) = NetVolume (m3) | Massa (kg) | Perimeter (mm) | GrossArea (m2) | NetArea (m2) | GrossVolume (m3)
871913 | 01 eerste verdieping | 42.9096 | 107274 | 207.612 | 165.037 | 165.038 | 42.9096
873958 | 01 eerste verdieping | 194.546 | 486365 | 516.673 | 748.175 | 748.169 | 194.526
874934 | 01 eerste verdieping | 169.923 | 424808 | 522.706 | 653.525 | 653.501 | 169.916
875884 | 01 eerste verdieping | 36.6523 | 91630.8 | 172.897 | 140.97 | 140.97 | 36.6523
877857 | 01 eerste verdieping | 19.4298 | 48574.6 | 122.313 | 74.7302 | 74.7302 | 19.4298
879329 | 01 eerste verdieping | 80.3021 | 200755 | 257.283 | 312.702 | 308.854 | 81.3025
881558 | 01 eerste verdieping | 33.487 | 83717.4 | 177.615 | 128.796 | 128.796 | 33.4869
881813 | 01 eerste verdieping | 28.5893 | 71473.4 | 201.164 | 109.959 | 109.959 | 28.5893
881929 | 01 eerste verdieping | 14.1073 | 35268.3 | 99.6245 | 54.2589 | 54.2589 | 14.1073
881958 | 01 eerste verdieping | 9.54147 | 23853.7 | 132.724 | 43.5006 | 36.698 | 11.3101
920048 | 02 tweede verdieping | 196.02 | 490049 | 515.115 | 753.843 | 753.837 | 195.999
920073 | 02 tweede verdieping | 169.923 | 424808 | 522.706 | 653.525 | 653.501 | 169.916
920094 | 02 tweede verdieping | 37.4498 | 93624.4 | 172.897 | 144.038 | 144.038 | 37.4498 | BaseQuantities - Width: 18609.5 mm
920171 | 02 tweede verdieping | 76.5878 | 191470 | 257.283 | 294.569 | 294.569 | 76.5878
920188 | 02 tweede verdieping | 19.4298 | 48574.6 | 122.313 | 74.7302 | 74.7302 | 19.4298
920245 | 02 tweede verdieping | 7.32514 | 18312.8 | 106.824 | 66.0996 | 28.1736 | 17.1859
924087 | 02 tweede verdieping | 40.2046 | 100512 | 205.775 | 171.913 | 154.635 | 44.6974
935154 | 02 tweede verdieping | 33.487 | 83717.4 | 177.615 | 128.796 | 128.796 | 33.4869
935243 | 02 tweede verdieping | 11.1802 | 27950.5 | 93.2415 | 43.0008 | 43.0008 | 11.1802 | BaseQuantities - Width: 4370 mm
948223 | 02 tweede verdieping | 19.4298 | 48574.6 | 122.313 | 74.7302 | 74.7302 | 19.4298
1069388 | 02 tweede verdieping | 14.6628 | 36657 | 101.919 | 56.3908 | 56.3947 | 14.6616
1070545 | 02 tweede verdieping | 27.8116 | 69529.1 | 183.61 | 113.77 | 106.968 | 29.5803
1070794 | 02 tweede verdieping | 16.997 | 42492.6 | 134.802 | 65.3732 | 65.3732 | 16.997

# IfcSlab: NLRS_23_FL_kanaalplaatvloer 320_gen_AT (2)
In: 01 eerste verdieping
Type - PredefinedType: FLOOR; Material: f2_beton_prefab_gen 320 mm
Classification: 23.21 vloeren; constructief, vrijdragende vloeren (Uniformat)
Tielemans_Floor_PSET - Soortelijk_gewicht: 2500 kg/m3; Type: NLRS_23_FL_kanaalplaatvloer 320_gen_AT; Description: kpv320+gewapdrkl 60; Structural Material: f2_beton_prefab_gen; Sterkteklasse: gen; Assembly Code: 23.21; Assembly Description: vloeren; constructief, vrijdragende vloeren; Structural: yes; Phase Created: 2. nieuwbouw
Name (Floor:NLRS_23_FL_kanaalplaatvloer 320_gen_AT:...) | Volume (m3) = NetVolume (m3) | Massa (kg) | Perimeter (mm) | GrossArea (m2) = NetArea (m2) | GrossVolume (m3)
871637 | 84.6775 | 211694 | 231.43 | 264.617 | 84.6775 | BaseQuantities - Width: 24445 mm
871767 | 84.3819 | 210955 | 229.999 | 263.693 | 84.3818

# IfcSlab: NLRS_27_FL_stalendakplaat 106_gen_AT, Floor:NLRS_27_FL_stalendakplaat 106_gen_AT:988893
In: 03 derde verdieping
Type - PredefinedType: FLOOR; Material: h2_staalplaat 108 mm
Classification: 27.21 daken; constructief, vlakke daken (Uniformat)
Tielemans_Floor_PSET - Soortelijk_gewicht: 8000 kg/m3; Structural: yes; Type: NLRS_27_FL_stalendakplaat 106_gen_AT; Description: stalendakplaat d=106; Structural Material: h2_staalplaat; Staalkwaliteit: Not Found; Assembly Code: 27.21; Assembly Description: daken; constructief, vlakke daken; Phase Created: 2. nieuwbouw; Volume: 14.3026 m3; Massa: 114421 kg
BaseQuantities - Perimeter: 153.868 mm; GrossArea: 132.425 m2; NetArea: 132.425 m2; GrossVolume: 14.3019 m3; NetVolume: 14.3026 m3

# IfcSlab: NLRS_27_FL_stalendakplaat 158 t=1,25_gen_AT (2)
In: 03 derde verdieping
Type - PredefinedType: FLOOR; Material: h2_staalplaat 158.1 mm
Classification: 27.21 daken; constructief, vlakke daken (Uniformat)
Tielemans_Floor_PSET - Soortelijk_gewicht: 8000 kg/m3; Structural: yes; Type: NLRS_27_FL_stalendakplaat 158 t=1,25_gen_AT; Description: stalendakplaat d=158R, t=1,25; Structural Material: h2_staalplaat; Staalkwaliteit: Not Found; Assembly Code: 27.21; Assembly Description: daken; constructief, vlakke daken; Phase Created: 2. nieuwbouw
Name (Floor:NLRS_27_FL_stalendakplaat 158 t=1,25_gen_AT:...) | Volume (m3) = NetVolume (m3) | Massa (kg) | Perimeter (mm) | GrossArea (m2) | NetArea (m2) | GrossVolume (m3)
972965 | 62.5709 | 500567 | 301.424 | 395.719 | 395.77 | 62.5631
973227 | 92.8094 | 742476 | 349.354 | 586.955 | 587.03 | 92.7975

# IfcWall: NLRS_22_WA_kalkzandsteen 214_CS20_gen_AT (8)
In: 01 eerste verdieping
Type - PredefinedType: STANDARD; Material: f1_kalkzandsteen_CS20 214 mm
Classification: 22.21 binnenwanden; constructief, massieve wanden (Uniformat)
Tielemans_Wall_PSET - Structural Usage: Bearing; Soortelijk_gewicht: 1850 kg/m3; Type: NLRS_22_WA_kalkzandsteen 214_CS20_gen_AT; Structural Material: f1_kalkzandsteen_CS20; Genormaliseerde steendruksterkte: CS20; Assembly Code: 22.21; Assembly Description: binnenwanden; constructief, massieve wanden; Phase Created: 2. nieuwbouw
BaseQuantities - Width: 214 mm
Name (Basic Wall:NLRS_22_WA_kalkzandsteen 214_CS20_gen_AT:...) | Volume (m3) = NetVolume (m3) | Massa (kg) | Length (mm)
891935 | 9.39872 | 17387.6 | 27500
891950 | 9.39071 | 17372.8 | 28738.9
891962 | 15.5127 | 28698.5 | 23488.9
891969 | 9.39872 | 17387.6 | 27500
891983 | 11.1656 | 20656.3 | 27293.6
891996 | 5.88614 | 10889.4 | 12695.3
892010 | 3.10252 | 5739.66 | 5632
903177 | 4.57444 | 8462.71 | 8900

# IfcWall: NLRS_22_WA_kalkzandsteen 214_CS36 gen_AT (7)
In: 00 begane grond
Type - PredefinedType: STANDARD; Material: f1_kalkzandsteen_CS36 214 mm
Classification: 22.21 binnenwanden; constructief, massieve wanden (Uniformat)
Tielemans_Wall_PSET - Type: NLRS_22_WA_kalkzandsteen 214_CS36 gen_AT; Structural Material: f1_kalkzandsteen_CS36; Genormaliseerde steendruksterkte: CS36; Assembly Code: 22.21; Assembly Description: binnenwanden; constructief, massieve wanden; Structural Usage: Bearing; Phase Created: 2. nieuwbouw; Soortelijk_gewicht: 1850 kg/m3
BaseQuantities - Width: 214 mm
Name (Basic Wall:NLRS_22_WA_kalkzandsteen 214_CS36 gen_AT:...) | Volume (m3) = NetVolume (m3) | Massa (kg) | Length (mm)
824376 | 8.08177 | 14951.3 | 27500
830901 | 8.16551 | 15106.2 | 28738.9
831382 | 9.18632 | 16994.7 | 23488.9
832357 | 8.08177 | 14951.3 | 27500
832519 | 8.34428 | 15436.9 | 27293.6
833328 | 5.95316 | 11013.3 | 12695.3
865143 | 3.15292 | 5832.9 | 5739

# IfcWallStandardCase: NLRS_21_WA_beton ihw 400_gen_AT (15)
In: 00 begane grond
Type - PredefinedType: STANDARD; Material: f2_beton ihwg_gen 400 mm
Classification: 21.21 buitenwanden; constructief, massieve wanden (Uniformat)
BaseQuantities - Width: 400 mm
Tielemans_Wall_PSET - Structural Usage: Bearing; Soortelijk_gewicht: 2500 kg/m3; Type: NLRS_21_WA_beton ihw 400_gen_AT; Structural Material: f2_beton ihwg_gen; Sterkteklasse: gen; Assembly Code: 21.21; Assembly Description: buitenwanden; constructief, massieve wanden; Phase Created: 2. nieuwbouw
Name (Basic Wall:NLRS_21_WA_beton ihw 400_gen_AT:...) | Height (mm) | Length (mm) | GrossFootprintArea (m2) | GrossVolume (m3) = NetVolume (m3) = Volume (m3) | GrossSideArea (m2) = NetSideArea (m2) | Massa (kg)
993300 | 750 | 2860 | 1.144 | 0.858 | 2.145 | 2145
993382 | 750 | 3410 | 1.364 | 1.023 | 2.5575 | 2557.5
993429 | 750 | 2460 | 0.984 | 0.738 | 1.845 | 1845
995394 | 750 | 2400 | 0.96 | 0.72 | 1.8 | 1800
995395 | 750 | 2822 | 1.1288 | 0.8466 | 2.1165 | 2116.5
995396 | 750 | 2000 | 0.8 | 0.6 | 1.5 | 1500
995397 | 750 | 2422 | 0.9688 | 0.7266 | 1.8165 | 1816.5
995890 | 704 | 12275 | 4.91 | 3.45664 | 8.6416 | 8641.6
996350 | 704 | 12375 | 4.95 | 3.4848 | 8.712 | 8712
996561 | 704 | 11475 | 4.59 | 3.23136 | 8.0784 | 8078.4
996608 | 704 | 2150 | 0.86 | 0.60544 | 1.5136 | 1513.6
996620 | 704 | 7900 | 3.16 | 2.22464 | 5.5616 | 5561.6
996679 | 704 | 2950 | 1.18 | 0.83072 | 2.0768 | 2076.8
996819 | 704 | 1945 | 0.778 | 0.547712 | 1.36928 | 1369.28
996923 | 704 | 1730 | 0.692 | 0.487168 | 1.21792 | 1217.92

# IfcWallStandardCase: NLRS_22_WA_beton opstort ihw 220_gen_AT (15)
In: 02 tweede verdieping
Type - PredefinedType: STANDARD; Material: f2_beton ihwg_gen 220 mm
Classification: 22.21 binnenwanden; constructief, massieve wanden (Uniformat)
BaseQuantities - Height: 200 mm; Width: 220 mm
Tielemans_Wall_PSET - Structural Usage: Bearing; LoadBearing: yes; Soortelijk_gewicht: 2500 kg/m3; Type: NLRS_22_WA_beton opstort ihw 220_gen_AT; Structural Material: f2_beton ihwg_gen; Sterkteklasse: gen; Assembly Code: 22.21; Assembly Description: binnenwanden; constructief, massieve wanden; Phase Created: 2. nieuwbouw
Name (Basic Wall:NLRS_22_WA_beton opstort ihw 220_gen_AT:...) | Length (mm) | GrossFootprintArea (m2) | GrossVolume (m3) | GrossSideArea (m2) | NetSideArea (m2) | NetVolume (m3) = Volume (m3) | Genormaliseerde steendruksterkte | Massa (kg)
953516 | 32994.8 | 7.25632 | 1.45177 | 6.59897 | 6.59897 | 1.45126 | gen | 3628.16
954158 | 1712.17 | 0.376027 |  |  | 0.376992 | 0.0753355 | gen | 188.339
960125 | 9112.5 | 2.00432 | 0.40095 | 1.8225 | 1.8225 | 0.400864 | gen | 1002.16
961185 | 1753.22 | 0.384762 |  |  | 0.383389 | 0.0769958 |  | 192.49
961622 | 27075 | 5.95528 | 1.1913 | 5.415 | 5.415 | 1.19106 | gen | 2977.64
965676 | 1557.45 | 0.339756 |  |  | 0.340579 | 0.067947 |  | 169.868
977072 | 13840 | 3.0448 | 0.60896 | 2.768 | 2.768 | 0.60896 | gen | 1522.4
977717 | 13840.3 | 3.04487 | 0.608973 | 2.76806 | 2.76806 | 0.608973 | gen | 1522.43
977809 | 5840 | 1.2848 | 0.25696 | 1.168 | 1.168 | 0.25696 | gen | 642.4
978946 | 1712.17 | 0.376027 |  |  | 0.376991 | 0.075336 |  | 188.34
979069 | 5840 | 1.2848 | 0.25696 | 1.168 | 1.168 | 0.25696 | gen | 642.4
979392 | 1711.87 | 0.375961 |  |  | 0.376925 | 0.0753556 |  | 188.389
979920 | 1712.17 | 0.376027 |  |  | 0.376991 | 0.0753688 |  | 188.422
979921 | 1712.17 | 0.376027 |  |  | 0.376991 | 0.075336 |  | 188.34
1013741 | 5795.66 | 1.27505 | 0.255009 | 1.15913 | 1.15913 | 0.255009 | gen | 637.523

# IfcWallStandardCase: NLRS_22_WA_kalkzandsteen 100_gen_AT (6)
In: 01 eerste verdieping
Type - PredefinedType: STANDARD; Material: f1_kalkzandsteen_gen 100 mm
Classification: 22.21 binnenwanden; constructief, massieve wanden (Uniformat)
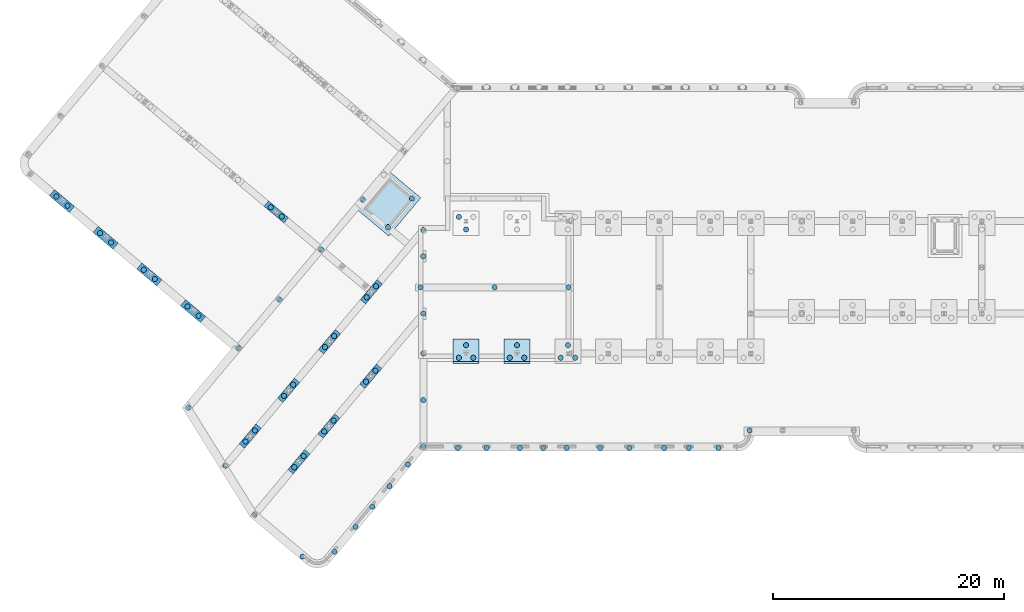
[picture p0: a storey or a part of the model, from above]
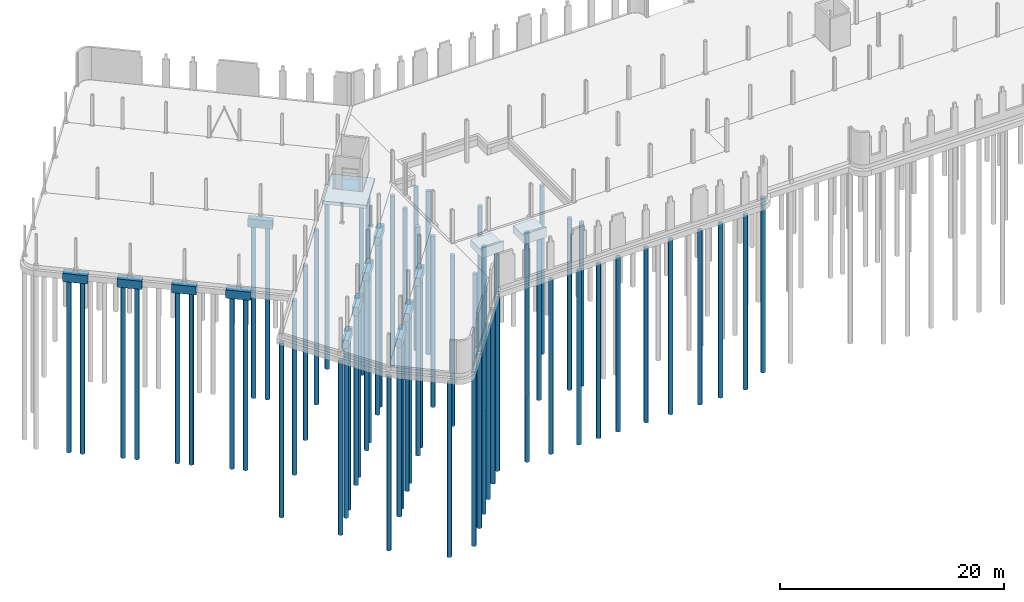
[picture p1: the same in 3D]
Properties of the parts of a building model (IFC2X3), part 3 of 3

# IfcWallStandardCase: NLRS_22_WA_kalkzandsteen 100_gen_AT (6)
BaseQuantities - Height: 1874 mm; Width: 100 mm
Tielemans_Wall_PSET - Structural Usage: Bearing; Soortelijk_gewicht: 1850 kg/m3; Type: NLRS_22_WA_kalkzandsteen 100_gen_AT; Structural Material: f1_kalkzandsteen_gen; Genormaliseerde steendruksterkte: gen; Assembly Code: 22.21; Assembly Description: binnenwanden; constructief, massieve wanden; Phase Created: 2. nieuwbouw
Name (Basic Wall:NLRS_22_WA_kalkzandsteen 100_gen_AT:...) | Length (mm) | GrossFootprintArea (m2) | GrossVolume (m3) = NetVolume (m3) = Volume (m3) | GrossSideArea (m2) = NetSideArea (m2) | Massa (kg)
1074153 | 1380 | 0.138 | 0.258612 | 2.58612 | 478.432
1074308 | 1200 | 0.12 | 0.22488 | 2.2488 | 416.028
1074393 | 2200 | 0.22 | 0.41228 | 4.1228 | 762.718
1074584 | 1203.64 | 0.120364 | 0.225562 | 2.25562 | 417.29
1074585 | 1376.36 | 0.137636 | 0.25793 | 2.5793 | 477.17
1074586 | 2200 | 0.22 | 0.41228 | 4.1228 | 762.718

# IfcWallStandardCase: NLRS_22_WA_kalkzandsteen 214_CS20_gen_AT (34)
Type - PredefinedType: STANDARD; Material: f1_kalkzandsteen_CS20 214 mm
Classification: 22.21 binnenwanden; constructief, massieve wanden (Uniformat)
BaseQuantities - Width: 214 mm
Tielemans_Wall_PSET - Structural Usage: Bearing; Soortelijk_gewicht: 1850 kg/m3; Type: NLRS_22_WA_kalkzandsteen 214_CS20_gen_AT; Structural Material: f1_kalkzandsteen_CS20; Genormaliseerde steendruksterkte: CS20; Assembly Code: 22.21; Assembly Description: binnenwanden; constructief, massieve wanden; Phase Created: 2. nieuwbouw
Name (Basic Wall:NLRS_22_WA_kalkzandsteen 214_CS20_gen_AT:...) | In | Height (mm) | Length (mm) | GrossFootprintArea (m2) | GrossVolume (m3) | GrossSideArea (m2) | NetSideArea (m2) | NetVolume (m3) = Volume (m3) | Massa (kg)
835175 | 00 begane grond | 3544 | 2514 | 0.537996 | 1.90666 | 8.90962 | 8.90962 | 1.90666 | 3527.32
835387 | 00 begane grond | 3544 | 3572 | 0.764408 | 2.70906 | 12.6592 | 12.4669 | 2.66791 | 4935.64
844884 | 00 begane grond | 3544 | 3438 | 0.735732 | 2.60743 | 12.1843 | 12.1843 | 2.60743 | 4823.75
845038 | 00 begane grond | 3544 | 3438 | 0.735732 | 2.60743 | 12.1843 | 12.1843 | 2.60743 | 4823.75
845110 | 00 begane grond | 3544 | 2260 | 0.48364 | 1.71402 | 8.00944 | 8.00944 | 1.71402 | 3170.94
845404 | 00 begane grond | 3544 | 2260 | 0.48364 | 0.9693 | 4.52944 | 4.52944 | 0.9693 | 1793.21
868245 | 00 begane grond | 3544 | 2028 | 0.433992 | 1.53807 | 7.18723 | 7.18723 | 1.53807 | 2845.43
868246 | 00 begane grond | 3544 | 2636 | 0.564104 | 1.99918 | 9.34198 | 9.34198 | 1.99918 | 3698.49
868247 | 00 begane grond | 3864 | 2636 | 0.564104 | 2.1797 | 10.1855 | 10.1855 | 2.1797 | 4032.44
868468 | 00 begane grond | 3544 | 1600 | 0.3424 | 0.674186 | 3.1504 | 3.1504 | 0.674186 | 1247.24
891936 | 01 eerste verdieping | 3544 | 1716.88 | 0.366765 |  |  | 6.68028 | 1.30212 | 2408.92
891937 | 01 eerste verdieping | 3544 | 1716.88 | 0.366765 |  |  | 6.68028 | 1.3027 | 2410
891938 | 01 eerste verdieping | 3544 | 1716.88 | 0.366765 |  |  | 6.68028 | 1.30212 | 2408.92
891970 | 01 eerste verdieping | 3544 | 1716.88 | 0.366765 |  |  | 6.68028 | 1.3027 | 2410
891971 | 01 eerste verdieping | 3544 | 1716.88 | 0.366765 |  |  | 6.68028 | 1.30212 | 2408.92
891984 | 01 eerste verdieping | 3544 | 1716.88 | 0.366765 |  |  | 6.68028 | 1.3027 | 2410
892001 | 01 eerste verdieping | 3544 | 1681.06 | 0.35939 |  |  | 6.54093 | 1.27366 | 2356.27
892002 | 01 eerste verdieping | 3544 | 2728 | 0.583792 | 2.06896 | 9.66803 | 9.66803 | 2.06896 | 3827.57
892003 | 01 eerste verdieping | 3544 | 3572 | 0.764408 | 2.70906 | 12.6592 | 12.6592 | 2.70906 | 5011.76
892004 | 01 eerste verdieping | 3544 | 3438 | 0.735732 | 2.60743 | 12.1843 | 12.1843 | 2.60743 | 4823.75
892005 | 01 eerste verdieping | 3544 | 3438 | 0.735732 | 2.60743 | 12.1843 | 12.1843 | 2.60743 | 4823.75
892006 | 01 eerste verdieping | 3544 | 2260 | 0.48364 | 1.71402 | 8.00944 | 8.00944 | 1.71402 | 3170.94
892007 | 01 eerste verdieping | 3544 | 2260 | 0.48364 | 0.9693 | 4.52944 | 4.52944 | 0.9693 | 1793.21
892008 | 01 eerste verdieping | 3544 | 645.059 | 0.138043 | 0.489223 | 2.28609 | 2.28609 | 0.489223 | 905.063
892009 | 01 eerste verdieping | 3544 | 1716.88 | 0.366765 |  |  | 6.68028 | 1.30211 | 2408.9
892012 | 01 eerste verdieping | 3544 | 2028 | 0.433992 | 1.53807 | 7.18723 | 7.18723 | 1.53807 | 2845.43
892013 | 01 eerste verdieping | 3544 | 2636 | 0.564104 | 1.99918 | 9.34198 | 9.34198 | 1.99918 | 3698.49
892014 | 01 eerste verdieping | 3544 | 2636 | 0.564104 | 1.99918 | 9.34198 | 9.34198 | 1.99918 | 3698.49
892015 | 01 eerste verdieping | 3544 | 1600 | 0.3424 | 0.674186 | 3.1504 | 3.1504 | 0.674186 | 1247.24
904171 | 01 eerste verdieping | 3544 | 1716.88 | 0.366765 |  |  | 6.68028 | 1.29546 | 2396.61
935054 | 02 tweede verdieping | 3995 | 3438 | 0.735732 | 2.93925 | 13.7348 | 13.7348 | 2.93925 | 5437.61
935055 | 02 tweede verdieping | 3995 | 3438 | 0.735732 | 2.93925 | 13.7348 | 13.7348 | 2.93925 | 5437.61
935056 | 02 tweede verdieping | 3995 | 2260 | 0.48364 | 1.93214 | 9.0287 | 9.0287 | 1.93214 | 3574.46
935057 | 02 tweede verdieping | 3995 | 2260 | 0.48364 | 1.18742 | 5.5487 | 5.5487 | 1.18742 | 2196.73

# IfcWallStandardCase: NLRS_22_WA_kalkzandsteen 214_CS36 gen_AT (9)
In: 00 begane grond
Type - PredefinedType: STANDARD; Material: f1_kalkzandsteen_CS36 214 mm
Classification: 22.21 binnenwanden; constructief, massieve wanden (Uniformat)
BaseQuantities - Height: 3544 mm; Width: 214 mm
Tielemans_Wall_PSET - Structural Usage: Bearing; Soortelijk_gewicht: 1850 kg/m3; Type: NLRS_22_WA_kalkzandsteen 214_CS36 gen_AT; Structural Material: f1_kalkzandsteen_CS36; Genormaliseerde steendruksterkte: CS36; Assembly Code: 22.21; Assembly Description: binnenwanden; constructief, massieve wanden; Phase Created: 2. nieuwbouw
Name (Basic Wall:NLRS_22_WA_kalkzandsteen 214_CS36 gen_AT:...) | Length (mm) | GrossFootprintArea (m2) | NetSideArea (m2) | NetVolume (m3) = Volume (m3) | Massa (kg)
824773 | 1716.88 | 0.366765 | 6.68028 | 1.30212 | 2408.92
824927 | 1716.88 | 0.366765 | 6.68028 | 1.3027 | 2410
825081 | 1716.88 | 0.366765 | 6.68028 | 1.30212 | 2408.92
832358 | 1716.88 | 0.366765 | 6.68028 | 1.3027 | 2410
832359 | 1716.88 | 0.366765 | 6.68028 | 1.30212 | 2408.92
832520 | 1716.88 | 0.366765 | 6.68028 | 1.3027 | 2410
834525 | 1681.06 | 0.35939 | 6.54093 | 1.27366 | 2356.27
851656 | 645.059 | 0.138043 | 2.28609 | 0.489223 | 905.063 | BaseQuantities - GrossVolume: 0.489223 m3; GrossSideArea: 2.28609 m2
858703 | 1716.88 | 0.366765 | 6.68028 | 1.30211 | 2408.9
